VERSION 5.7 ;
  NOWIREEXTENSIONATPIN ON ;
  DIVIDERCHAR "/" ;
  BUSBITCHARS "[]" ;
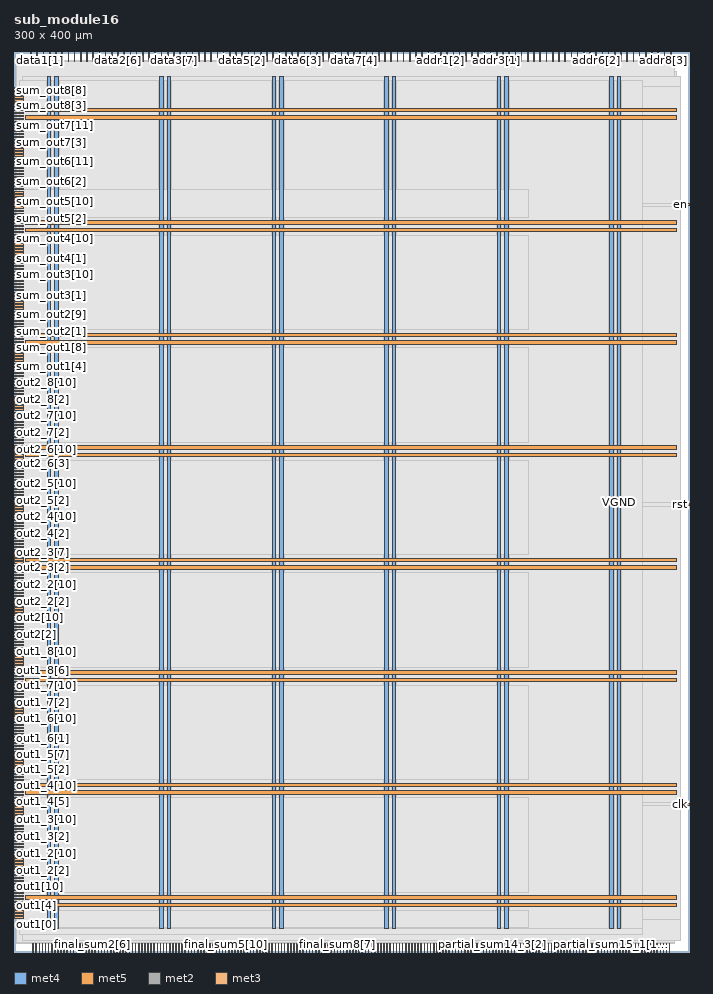
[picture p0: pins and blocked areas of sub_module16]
MACRO sub_module16
  CLASS BLOCK ;
  FOREIGN sub_module16 ;
  ORIGIN 0.000 0.000 ;
  SIZE 300.000 BY 400.000 ;
  PIN VGND
    DIRECTION INOUT ;
    USE GROUND ;
    PORT
      LAYER met4 ;
        RECT 18.020 10.640 19.620 389.200 ;
    END
    PORT
      LAYER met4 ;
        RECT 68.020 10.640 69.620 389.200 ;
    END
    PORT
      LAYER met4 ;
        RECT 118.020 10.640 119.620 389.200 ;
    END
    PORT
      LAYER met4 ;
        RECT 168.020 10.640 169.620 389.200 ;
    END
    PORT
      LAYER met4 ;
        RECT 218.020 10.640 219.620 389.200 ;
    END
    PORT
      LAYER met4 ;
        RECT 268.020 10.640 269.620 389.200 ;
    END
    PORT
      LAYER met5 ;
        RECT 5.280 23.380 294.640 24.980 ;
    END
    PORT
      LAYER met5 ;
        RECT 5.280 73.380 294.640 74.980 ;
    END
    PORT
      LAYER met5 ;
        RECT 5.280 123.380 294.640 124.980 ;
    END
    PORT
      LAYER met5 ;
        RECT 5.280 173.380 294.640 174.980 ;
    END
    PORT
      LAYER met5 ;
        RECT 5.280 223.380 294.640 224.980 ;
    END
    PORT
      LAYER met5 ;
        RECT 5.280 273.380 294.640 274.980 ;
    END
    PORT
      LAYER met5 ;
        RECT 5.280 323.380 294.640 324.980 ;
    END
    PORT
      LAYER met5 ;
        RECT 5.280 373.380 294.640 374.980 ;
    END
  END VGND
  PIN VPWR
    DIRECTION INOUT ;
    USE POWER ;
    PORT
      LAYER met4 ;
        RECT 14.720 10.640 16.320 389.200 ;
    END
    PORT
      LAYER met4 ;
        RECT 64.720 10.640 66.320 389.200 ;
    END
    PORT
      LAYER met4 ;
        RECT 114.720 10.640 116.320 389.200 ;
    END
    PORT
      LAYER met4 ;
        RECT 164.720 10.640 166.320 389.200 ;
    END
    PORT
      LAYER met4 ;
        RECT 214.720 10.640 216.320 389.200 ;
    END
    PORT
      LAYER met4 ;
        RECT 264.720 10.640 266.320 389.200 ;
    END
    PORT
      LAYER met5 ;
        RECT 5.280 20.080 294.640 21.680 ;
    END
    PORT
      LAYER met5 ;
        RECT 5.280 70.080 294.640 71.680 ;
    END
    PORT
      LAYER met5 ;
        RECT 5.280 120.080 294.640 121.680 ;
    END
    PORT
      LAYER met5 ;
        RECT 5.280 170.080 294.640 171.680 ;
    END
    PORT
      LAYER met5 ;
        RECT 5.280 220.080 294.640 221.680 ;
    END
    PORT
      LAYER met5 ;
        RECT 5.280 270.080 294.640 271.680 ;
    END
    PORT
      LAYER met5 ;
        RECT 5.280 320.080 294.640 321.680 ;
    END
    PORT
      LAYER met5 ;
        RECT 5.280 370.080 294.640 371.680 ;
    END
  END VPWR
  PIN addr1[0]
    DIRECTION INPUT ;
    USE SIGNAL ;
    ANTENNAGATEAREA 0.213000 ;
    PORT
      LAYER met2 ;
        RECT 184.090 396.000 184.370 400.000 ;
    END
  END addr1[0]
  PIN addr1[1]
    DIRECTION INPUT ;
    USE SIGNAL ;
    ANTENNAGATEAREA 0.213000 ;
    PORT
      LAYER met2 ;
        RECT 186.850 396.000 187.130 400.000 ;
    END
  END addr1[1]
  PIN addr1[2]
    DIRECTION INPUT ;
    USE SIGNAL ;
    ANTENNAGATEAREA 0.247500 ;
    PORT
      LAYER met2 ;
        RECT 189.610 396.000 189.890 400.000 ;
    END
  END addr1[2]
  PIN addr1[3]
    DIRECTION INPUT ;
    USE SIGNAL ;
    ANTENNAGATEAREA 0.159000 ;
    PORT
      LAYER met2 ;
        RECT 192.370 396.000 192.650 400.000 ;
    END
  END addr1[3]
  PIN addr1[4]
    DIRECTION INPUT ;
    USE SIGNAL ;
    ANTENNAGATEAREA 0.159000 ;
    PORT
      LAYER met2 ;
        RECT 195.130 396.000 195.410 400.000 ;
    END
  END addr1[4]
  PIN addr2[0]
    DIRECTION INPUT ;
    USE SIGNAL ;
    ANTENNAGATEAREA 0.213000 ;
    PORT
      LAYER met2 ;
        RECT 197.890 396.000 198.170 400.000 ;
    END
  END addr2[0]
  PIN addr2[1]
    DIRECTION INPUT ;
    USE SIGNAL ;
    ANTENNAGATEAREA 0.159000 ;
    PORT
      LAYER met2 ;
        RECT 200.650 396.000 200.930 400.000 ;
    END
  END addr2[1]
  PIN addr2[2]
    DIRECTION INPUT ;
    USE SIGNAL ;
    ANTENNAGATEAREA 0.247500 ;
    PORT
      LAYER met2 ;
        RECT 203.410 396.000 203.690 400.000 ;
    END
  END addr2[2]
  PIN addr2[3]
    DIRECTION INPUT ;
    USE SIGNAL ;
    ANTENNAGATEAREA 0.213000 ;
    PORT
      LAYER met2 ;
        RECT 206.170 396.000 206.450 400.000 ;
    END
  END addr2[3]
  PIN addr2[4]
    DIRECTION INPUT ;
    USE SIGNAL ;
    ANTENNAGATEAREA 0.159000 ;
    PORT
      LAYER met2 ;
        RECT 208.930 396.000 209.210 400.000 ;
    END
  END addr2[4]
  PIN addr3[0]
    DIRECTION INPUT ;
    USE SIGNAL ;
    ANTENNAGATEAREA 0.159000 ;
    PORT
      LAYER met2 ;
        RECT 211.690 396.000 211.970 400.000 ;
    END
  END addr3[0]
  PIN addr3[1]
    DIRECTION INPUT ;
    USE SIGNAL ;
    ANTENNAGATEAREA 0.213000 ;
    PORT
      LAYER met2 ;
        RECT 214.450 396.000 214.730 400.000 ;
    END
  END addr3[1]
  PIN addr3[2]
    DIRECTION INPUT ;
    USE SIGNAL ;
    ANTENNAGATEAREA 0.159000 ;
    PORT
      LAYER met2 ;
        RECT 217.210 396.000 217.490 400.000 ;
    END
  END addr3[2]
  PIN addr3[3]
    DIRECTION INPUT ;
    USE SIGNAL ;
    ANTENNAGATEAREA 0.213000 ;
    PORT
      LAYER met2 ;
        RECT 219.970 396.000 220.250 400.000 ;
    END
  END addr3[3]
  PIN addr3[4]
    DIRECTION INPUT ;
    USE SIGNAL ;
    ANTENNAGATEAREA 0.213000 ;
    PORT
      LAYER met2 ;
        RECT 222.730 396.000 223.010 400.000 ;
    END
  END addr3[4]
  PIN addr4[0]
    DIRECTION INPUT ;
    USE SIGNAL ;
    ANTENNAGATEAREA 0.213000 ;
    PORT
      LAYER met2 ;
        RECT 225.490 396.000 225.770 400.000 ;
    END
  END addr4[0]
  PIN addr4[1]
    DIRECTION INPUT ;
    USE SIGNAL ;
    ANTENNAGATEAREA 0.159000 ;
    PORT
      LAYER met2 ;
        RECT 228.250 396.000 228.530 400.000 ;
    END
  END addr4[1]
  PIN addr4[2]
    DIRECTION INPUT ;
    USE SIGNAL ;
    ANTENNAGATEAREA 0.213000 ;
    PORT
      LAYER met2 ;
        RECT 231.010 396.000 231.290 400.000 ;
    END
  END addr4[2]
  PIN addr4[3]
    DIRECTION INPUT ;
    USE SIGNAL ;
    ANTENNAGATEAREA 0.159000 ;
    PORT
      LAYER met2 ;
        RECT 233.770 396.000 234.050 400.000 ;
    END
  END addr4[3]
  PIN addr4[4]
    DIRECTION INPUT ;
    USE SIGNAL ;
    ANTENNAGATEAREA 0.213000 ;
    PORT
      LAYER met2 ;
        RECT 236.530 396.000 236.810 400.000 ;
    END
  END addr4[4]
  PIN addr5[0]
    DIRECTION INPUT ;
    USE SIGNAL ;
    ANTENNAGATEAREA 0.213000 ;
    PORT
      LAYER met2 ;
        RECT 239.290 396.000 239.570 400.000 ;
    END
  END addr5[0]
  PIN addr5[1]
    DIRECTION INPUT ;
    USE SIGNAL ;
    ANTENNAGATEAREA 0.213000 ;
    PORT
      LAYER met2 ;
        RECT 242.050 396.000 242.330 400.000 ;
    END
  END addr5[1]
  PIN addr5[2]
    DIRECTION INPUT ;
    USE SIGNAL ;
    ANTENNAGATEAREA 0.213000 ;
    PORT
      LAYER met2 ;
        RECT 244.810 396.000 245.090 400.000 ;
    END
  END addr5[2]
  PIN addr5[3]
    DIRECTION INPUT ;
    USE SIGNAL ;
    ANTENNAGATEAREA 0.159000 ;
    PORT
      LAYER met2 ;
        RECT 247.570 396.000 247.850 400.000 ;
    END
  END addr5[3]
  PIN addr5[4]
    DIRECTION INPUT ;
    USE SIGNAL ;
    ANTENNAGATEAREA 0.247500 ;
    PORT
      LAYER met2 ;
        RECT 250.330 396.000 250.610 400.000 ;
    END
  END addr5[4]
  PIN addr6[0]
    DIRECTION INPUT ;
    USE SIGNAL ;
    ANTENNAGATEAREA 0.213000 ;
    PORT
      LAYER met2 ;
        RECT 253.090 396.000 253.370 400.000 ;
    END
  END addr6[0]
  PIN addr6[1]
    DIRECTION INPUT ;
    USE SIGNAL ;
    ANTENNAGATEAREA 0.159000 ;
    PORT
      LAYER met2 ;
        RECT 255.850 396.000 256.130 400.000 ;
    END
  END addr6[1]
  PIN addr6[2]
    DIRECTION INPUT ;
    USE SIGNAL ;
    ANTENNAGATEAREA 0.159000 ;
    PORT
      LAYER met2 ;
        RECT 258.610 396.000 258.890 400.000 ;
    END
  END addr6[2]
  PIN addr6[3]
    DIRECTION INPUT ;
    USE SIGNAL ;
    ANTENNAGATEAREA 0.213000 ;
    PORT
      LAYER met2 ;
        RECT 261.370 396.000 261.650 400.000 ;
    END
  END addr6[3]
  PIN addr6[4]
    DIRECTION INPUT ;
    USE SIGNAL ;
    ANTENNAGATEAREA 0.213000 ;
    PORT
      LAYER met2 ;
        RECT 264.130 396.000 264.410 400.000 ;
    END
  END addr6[4]
  PIN addr7[0]
    DIRECTION INPUT ;
    USE SIGNAL ;
    ANTENNAGATEAREA 0.196500 ;
    PORT
      LAYER met2 ;
        RECT 266.890 396.000 267.170 400.000 ;
    END
  END addr7[0]
  PIN addr7[1]
    DIRECTION INPUT ;
    USE SIGNAL ;
    ANTENNAGATEAREA 0.196500 ;
    PORT
      LAYER met2 ;
        RECT 269.650 396.000 269.930 400.000 ;
    END
  END addr7[1]
  PIN addr7[2]
    DIRECTION INPUT ;
    USE SIGNAL ;
    ANTENNAGATEAREA 0.213000 ;
    PORT
      LAYER met2 ;
        RECT 272.410 396.000 272.690 400.000 ;
    END
  END addr7[2]
  PIN addr7[3]
    DIRECTION INPUT ;
    USE SIGNAL ;
    ANTENNAGATEAREA 0.159000 ;
    PORT
      LAYER met2 ;
        RECT 275.170 396.000 275.450 400.000 ;
    END
  END addr7[3]
  PIN addr7[4]
    DIRECTION INPUT ;
    USE SIGNAL ;
    ANTENNAGATEAREA 0.213000 ;
    PORT
      LAYER met2 ;
        RECT 277.930 396.000 278.210 400.000 ;
    END
  END addr7[4]
  PIN addr8[0]
    DIRECTION INPUT ;
    USE SIGNAL ;
    ANTENNAGATEAREA 0.159000 ;
    PORT
      LAYER met2 ;
        RECT 280.690 396.000 280.970 400.000 ;
    END
  END addr8[0]
  PIN addr8[1]
    DIRECTION INPUT ;
    USE SIGNAL ;
    ANTENNAGATEAREA 0.213000 ;
    PORT
      LAYER met2 ;
        RECT 283.450 396.000 283.730 400.000 ;
    END
  END addr8[1]
  PIN addr8[2]
    DIRECTION INPUT ;
    USE SIGNAL ;
    ANTENNAGATEAREA 0.126000 ;
    PORT
      LAYER met2 ;
        RECT 286.210 396.000 286.490 400.000 ;
    END
  END addr8[2]
  PIN addr8[3]
    DIRECTION INPUT ;
    USE SIGNAL ;
    ANTENNAGATEAREA 0.159000 ;
    PORT
      LAYER met2 ;
        RECT 288.970 396.000 289.250 400.000 ;
    END
  END addr8[3]
  PIN addr8[4]
    DIRECTION INPUT ;
    USE SIGNAL ;
    ANTENNAGATEAREA 0.247500 ;
    PORT
      LAYER met2 ;
        RECT 291.730 396.000 292.010 400.000 ;
    END
  END addr8[4]
  PIN clk
    DIRECTION INPUT ;
    USE SIGNAL ;
    ANTENNAGATEAREA 0.852000 ;
    PORT
      LAYER met3 ;
        RECT 296.000 65.320 300.000 65.920 ;
    END
  END clk
  PIN data1[0]
    DIRECTION INPUT ;
    USE SIGNAL ;
    ANTENNAGATEAREA 0.159000 ;
    PORT
      LAYER met2 ;
        RECT 7.450 396.000 7.730 400.000 ;
    END
  END data1[0]
  PIN data1[1]
    DIRECTION INPUT ;
    USE SIGNAL ;
    ANTENNAGATEAREA 0.159000 ;
    PORT
      LAYER met2 ;
        RECT 10.210 396.000 10.490 400.000 ;
    END
  END data1[1]
  PIN data1[2]
    DIRECTION INPUT ;
    USE SIGNAL ;
    ANTENNAGATEAREA 0.213000 ;
    PORT
      LAYER met2 ;
        RECT 12.970 396.000 13.250 400.000 ;
    END
  END data1[2]
  PIN data1[3]
    DIRECTION INPUT ;
    USE SIGNAL ;
    ANTENNAGATEAREA 0.159000 ;
    PORT
      LAYER met2 ;
        RECT 15.730 396.000 16.010 400.000 ;
    END
  END data1[3]
  PIN data1[4]
    DIRECTION INPUT ;
    USE SIGNAL ;
    ANTENNAGATEAREA 0.159000 ;
    PORT
      LAYER met2 ;
        RECT 18.490 396.000 18.770 400.000 ;
    END
  END data1[4]
  PIN data1[5]
    DIRECTION INPUT ;
    USE SIGNAL ;
    ANTENNAGATEAREA 0.159000 ;
    PORT
      LAYER met2 ;
        RECT 21.250 396.000 21.530 400.000 ;
    END
  END data1[5]
  PIN data1[6]
    DIRECTION INPUT ;
    USE SIGNAL ;
    ANTENNAGATEAREA 0.159000 ;
    PORT
      LAYER met2 ;
        RECT 24.010 396.000 24.290 400.000 ;
    END
  END data1[6]
  PIN data1[7]
    DIRECTION INPUT ;
    USE SIGNAL ;
    ANTENNAGATEAREA 0.159000 ;
    PORT
      LAYER met2 ;
        RECT 26.770 396.000 27.050 400.000 ;
    END
  END data1[7]
  PIN data2[0]
    DIRECTION INPUT ;
    USE SIGNAL ;
    ANTENNAGATEAREA 0.159000 ;
    PORT
      LAYER met2 ;
        RECT 29.530 396.000 29.810 400.000 ;
    END
  END data2[0]
  PIN data2[1]
    DIRECTION INPUT ;
    USE SIGNAL ;
    ANTENNAGATEAREA 0.159000 ;
    PORT
      LAYER met2 ;
        RECT 32.290 396.000 32.570 400.000 ;
    END
  END data2[1]
  PIN data2[2]
    DIRECTION INPUT ;
    USE SIGNAL ;
    ANTENNAGATEAREA 0.159000 ;
    PORT
      LAYER met2 ;
        RECT 35.050 396.000 35.330 400.000 ;
    END
  END data2[2]
  PIN data2[3]
    DIRECTION INPUT ;
    USE SIGNAL ;
    ANTENNAGATEAREA 0.159000 ;
    PORT
      LAYER met2 ;
        RECT 37.810 396.000 38.090 400.000 ;
    END
  END data2[3]
  PIN data2[4]
    DIRECTION INPUT ;
    USE SIGNAL ;
    ANTENNAGATEAREA 0.159000 ;
    PORT
      LAYER met2 ;
        RECT 40.570 396.000 40.850 400.000 ;
    END
  END data2[4]
  PIN data2[5]
    DIRECTION INPUT ;
    USE SIGNAL ;
    ANTENNAGATEAREA 0.159000 ;
    PORT
      LAYER met2 ;
        RECT 43.330 396.000 43.610 400.000 ;
    END
  END data2[5]
  PIN data2[6]
    DIRECTION INPUT ;
    USE SIGNAL ;
    ANTENNAGATEAREA 0.159000 ;
    PORT
      LAYER met2 ;
        RECT 46.090 396.000 46.370 400.000 ;
    END
  END data2[6]
  PIN data2[7]
    DIRECTION INPUT ;
    USE SIGNAL ;
    ANTENNAGATEAREA 0.159000 ;
    PORT
      LAYER met2 ;
        RECT 48.850 396.000 49.130 400.000 ;
    END
  END data2[7]
  PIN data3[0]
    DIRECTION INPUT ;
    USE SIGNAL ;
    ANTENNAGATEAREA 0.196500 ;
    PORT
      LAYER met2 ;
        RECT 51.610 396.000 51.890 400.000 ;
    END
  END data3[0]
  PIN data3[1]
    DIRECTION INPUT ;
    USE SIGNAL ;
    ANTENNAGATEAREA 0.196500 ;
    PORT
      LAYER met2 ;
        RECT 54.370 396.000 54.650 400.000 ;
    END
  END data3[1]
  PIN data3[2]
    DIRECTION INPUT ;
    USE SIGNAL ;
    ANTENNAGATEAREA 0.196500 ;
    PORT
      LAYER met2 ;
        RECT 57.130 396.000 57.410 400.000 ;
    END
  END data3[2]
  PIN data3[3]
    DIRECTION INPUT ;
    USE SIGNAL ;
    ANTENNAGATEAREA 0.196500 ;
    PORT
      LAYER met2 ;
        RECT 59.890 396.000 60.170 400.000 ;
    END
  END data3[3]
  PIN data3[4]
    DIRECTION INPUT ;
    USE SIGNAL ;
    ANTENNAGATEAREA 0.196500 ;
    PORT
      LAYER met2 ;
        RECT 62.650 396.000 62.930 400.000 ;
    END
  END data3[4]
  PIN data3[5]
    DIRECTION INPUT ;
    USE SIGNAL ;
    ANTENNAGATEAREA 0.196500 ;
    PORT
      LAYER met2 ;
        RECT 65.410 396.000 65.690 400.000 ;
    END
  END data3[5]
  PIN data3[6]
    DIRECTION INPUT ;
    USE SIGNAL ;
    ANTENNAGATEAREA 0.196500 ;
    PORT
      LAYER met2 ;
        RECT 68.170 396.000 68.450 400.000 ;
    END
  END data3[6]
  PIN data3[7]
    DIRECTION INPUT ;
    USE SIGNAL ;
    ANTENNAGATEAREA 0.196500 ;
    PORT
      LAYER met2 ;
        RECT 70.930 396.000 71.210 400.000 ;
    END
  END data3[7]
  PIN data4[0]
    DIRECTION INPUT ;
    USE SIGNAL ;
    ANTENNAGATEAREA 0.196500 ;
    PORT
      LAYER met2 ;
        RECT 73.690 396.000 73.970 400.000 ;
    END
  END data4[0]
  PIN data4[1]
    DIRECTION INPUT ;
    USE SIGNAL ;
    ANTENNAGATEAREA 0.196500 ;
    PORT
      LAYER met2 ;
        RECT 76.450 396.000 76.730 400.000 ;
    END
  END data4[1]
  PIN data4[2]
    DIRECTION INPUT ;
    USE SIGNAL ;
    ANTENNAGATEAREA 0.196500 ;
    PORT
      LAYER met2 ;
        RECT 79.210 396.000 79.490 400.000 ;
    END
  END data4[2]
  PIN data4[3]
    DIRECTION INPUT ;
    USE SIGNAL ;
    ANTENNAGATEAREA 0.196500 ;
    PORT
      LAYER met2 ;
        RECT 81.970 396.000 82.250 400.000 ;
    END
  END data4[3]
  PIN data4[4]
    DIRECTION INPUT ;
    USE SIGNAL ;
    ANTENNAGATEAREA 0.196500 ;
    PORT
      LAYER met2 ;
        RECT 84.730 396.000 85.010 400.000 ;
    END
  END data4[4]
  PIN data4[5]
    DIRECTION INPUT ;
    USE SIGNAL ;
    ANTENNAGATEAREA 0.196500 ;
    PORT
      LAYER met2 ;
        RECT 87.490 396.000 87.770 400.000 ;
    END
  END data4[5]
  PIN data4[6]
    DIRECTION INPUT ;
    USE SIGNAL ;
    ANTENNAGATEAREA 0.213000 ;
    PORT
      LAYER met2 ;
        RECT 90.250 396.000 90.530 400.000 ;
    END
  END data4[6]
  PIN data4[7]
    DIRECTION INPUT ;
    USE SIGNAL ;
    ANTENNAGATEAREA 0.213000 ;
    PORT
      LAYER met2 ;
        RECT 93.010 396.000 93.290 400.000 ;
    END
  END data4[7]
  PIN data5[0]
    DIRECTION INPUT ;
    USE SIGNAL ;
    ANTENNAGATEAREA 0.196500 ;
    PORT
      LAYER met2 ;
        RECT 95.770 396.000 96.050 400.000 ;
    END
  END data5[0]
  PIN data5[1]
    DIRECTION INPUT ;
    USE SIGNAL ;
    ANTENNAGATEAREA 0.196500 ;
    PORT
      LAYER met2 ;
        RECT 98.530 396.000 98.810 400.000 ;
    END
  END data5[1]
  PIN data5[2]
    DIRECTION INPUT ;
    USE SIGNAL ;
    ANTENNAGATEAREA 0.196500 ;
    PORT
      LAYER met2 ;
        RECT 101.290 396.000 101.570 400.000 ;
    END
  END data5[2]
  PIN data5[3]
    DIRECTION INPUT ;
    USE SIGNAL ;
    ANTENNAGATEAREA 0.196500 ;
    PORT
      LAYER met2 ;
        RECT 104.050 396.000 104.330 400.000 ;
    END
  END data5[3]
  PIN data5[4]
    DIRECTION INPUT ;
    USE SIGNAL ;
    ANTENNAGATEAREA 0.196500 ;
    PORT
      LAYER met2 ;
        RECT 106.810 396.000 107.090 400.000 ;
    END
  END data5[4]
  PIN data5[5]
    DIRECTION INPUT ;
    USE SIGNAL ;
    ANTENNAGATEAREA 0.196500 ;
    PORT
      LAYER met2 ;
        RECT 109.570 396.000 109.850 400.000 ;
    END
  END data5[5]
  PIN data5[6]
    DIRECTION INPUT ;
    USE SIGNAL ;
    ANTENNAGATEAREA 0.126000 ;
    PORT
      LAYER met2 ;
        RECT 112.330 396.000 112.610 400.000 ;
    END
  END data5[6]
  PIN data5[7]
    DIRECTION INPUT ;
    USE SIGNAL ;
    ANTENNAGATEAREA 0.126000 ;
    PORT
      LAYER met2 ;
        RECT 115.090 396.000 115.370 400.000 ;
    END
  END data5[7]
  PIN data6[0]
    DIRECTION INPUT ;
    USE SIGNAL ;
    ANTENNAGATEAREA 0.196500 ;
    PORT
      LAYER met2 ;
        RECT 117.850 396.000 118.130 400.000 ;
    END
  END data6[0]
  PIN data6[1]
    DIRECTION INPUT ;
    USE SIGNAL ;
    ANTENNAGATEAREA 0.196500 ;
    PORT
      LAYER met2 ;
        RECT 120.610 396.000 120.890 400.000 ;
    END
  END data6[1]
  PIN data6[2]
    DIRECTION INPUT ;
    USE SIGNAL ;
    ANTENNAGATEAREA 0.196500 ;
    PORT
      LAYER met2 ;
        RECT 123.370 396.000 123.650 400.000 ;
    END
  END data6[2]
  PIN data6[3]
    DIRECTION INPUT ;
    USE SIGNAL ;
    ANTENNAGATEAREA 0.196500 ;
    PORT
      LAYER met2 ;
        RECT 126.130 396.000 126.410 400.000 ;
    END
  END data6[3]
  PIN data6[4]
    DIRECTION INPUT ;
    USE SIGNAL ;
    ANTENNAGATEAREA 0.196500 ;
    PORT
      LAYER met2 ;
        RECT 128.890 396.000 129.170 400.000 ;
    END
  END data6[4]
  PIN data6[5]
    DIRECTION INPUT ;
    USE SIGNAL ;
    ANTENNAGATEAREA 0.196500 ;
    PORT
      LAYER met2 ;
        RECT 131.650 396.000 131.930 400.000 ;
    END
  END data6[5]
  PIN data6[6]
    DIRECTION INPUT ;
    USE SIGNAL ;
    ANTENNAGATEAREA 0.196500 ;
    PORT
      LAYER met2 ;
        RECT 134.410 396.000 134.690 400.000 ;
    END
  END data6[6]
  PIN data6[7]
    DIRECTION INPUT ;
    USE SIGNAL ;
    ANTENNAGATEAREA 0.196500 ;
    PORT
      LAYER met2 ;
        RECT 137.170 396.000 137.450 400.000 ;
    END
  END data6[7]
  PIN data7[0]
    DIRECTION INPUT ;
    USE SIGNAL ;
    ANTENNAGATEAREA 0.196500 ;
    PORT
      LAYER met2 ;
        RECT 139.930 396.000 140.210 400.000 ;
    END
  END data7[0]
  PIN data7[1]
    DIRECTION INPUT ;
    USE SIGNAL ;
    ANTENNAGATEAREA 0.196500 ;
    PORT
      LAYER met2 ;
        RECT 142.690 396.000 142.970 400.000 ;
    END
  END data7[1]
  PIN data7[2]
    DIRECTION INPUT ;
    USE SIGNAL ;
    ANTENNAGATEAREA 0.196500 ;
    PORT
      LAYER met2 ;
        RECT 145.450 396.000 145.730 400.000 ;
    END
  END data7[2]
  PIN data7[3]
    DIRECTION INPUT ;
    USE SIGNAL ;
    ANTENNAGATEAREA 0.196500 ;
    PORT
      LAYER met2 ;
        RECT 148.210 396.000 148.490 400.000 ;
    END
  END data7[3]
  PIN data7[4]
    DIRECTION INPUT ;
    USE SIGNAL ;
    ANTENNAGATEAREA 0.196500 ;
    PORT
      LAYER met2 ;
        RECT 150.970 396.000 151.250 400.000 ;
    END
  END data7[4]
  PIN data7[5]
    DIRECTION INPUT ;
    USE SIGNAL ;
    ANTENNAGATEAREA 0.196500 ;
    PORT
      LAYER met2 ;
        RECT 153.730 396.000 154.010 400.000 ;
    END
  END data7[5]
  PIN data7[6]
    DIRECTION INPUT ;
    USE SIGNAL ;
    ANTENNAGATEAREA 0.196500 ;
    PORT
      LAYER met2 ;
        RECT 156.490 396.000 156.770 400.000 ;
    END
  END data7[6]
  PIN data7[7]
    DIRECTION INPUT ;
    USE SIGNAL ;
    ANTENNAGATEAREA 0.196500 ;
    PORT
      LAYER met2 ;
        RECT 159.250 396.000 159.530 400.000 ;
    END
  END data7[7]
  PIN data8[0]
    DIRECTION INPUT ;
    USE SIGNAL ;
    ANTENNAGATEAREA 0.196500 ;
    PORT
      LAYER met2 ;
        RECT 162.010 396.000 162.290 400.000 ;
    END
  END data8[0]
  PIN data8[1]
    DIRECTION INPUT ;
    USE SIGNAL ;
    ANTENNAGATEAREA 0.196500 ;
    PORT
      LAYER met2 ;
        RECT 164.770 396.000 165.050 400.000 ;
    END
  END data8[1]
  PIN data8[2]
    DIRECTION INPUT ;
    USE SIGNAL ;
    ANTENNAGATEAREA 0.196500 ;
    PORT
      LAYER met2 ;
        RECT 167.530 396.000 167.810 400.000 ;
    END
  END data8[2]
  PIN data8[3]
    DIRECTION INPUT ;
    USE SIGNAL ;
    ANTENNAGATEAREA 0.196500 ;
    PORT
      LAYER met2 ;
        RECT 170.290 396.000 170.570 400.000 ;
    END
  END data8[3]
  PIN data8[4]
    DIRECTION INPUT ;
    USE SIGNAL ;
    ANTENNAGATEAREA 0.196500 ;
    PORT
      LAYER met2 ;
        RECT 173.050 396.000 173.330 400.000 ;
    END
  END data8[4]
  PIN data8[5]
    DIRECTION INPUT ;
    USE SIGNAL ;
    ANTENNAGATEAREA 0.196500 ;
    PORT
      LAYER met2 ;
        RECT 175.810 396.000 176.090 400.000 ;
    END
  END data8[5]
  PIN data8[6]
    DIRECTION INPUT ;
    USE SIGNAL ;
    ANTENNAGATEAREA 0.196500 ;
    PORT
      LAYER met2 ;
        RECT 178.570 396.000 178.850 400.000 ;
    END
  END data8[6]
  PIN data8[7]
    DIRECTION INPUT ;
    USE SIGNAL ;
    ANTENNAGATEAREA 0.196500 ;
    PORT
      LAYER met2 ;
        RECT 181.330 396.000 181.610 400.000 ;
    END
  END data8[7]
  PIN en
    DIRECTION INPUT ;
    USE SIGNAL ;
    ANTENNAGATEAREA 0.426000 ;
    PORT
      LAYER met3 ;
        RECT 296.000 331.880 300.000 332.480 ;
    END
  END en
  PIN final_sum1[0]
    DIRECTION OUTPUT ;
    USE SIGNAL ;
    ANTENNADIFFAREA 0.340600 ;
    PORT
      LAYER met2 ;
        RECT 8.370 0.000 8.650 4.000 ;
    END
  END final_sum1[0]
  PIN final_sum1[10]
    DIRECTION OUTPUT ;
    USE SIGNAL ;
    ANTENNADIFFAREA 0.340600 ;
    PORT
      LAYER met2 ;
        RECT 22.170 0.000 22.450 4.000 ;
    END
  END final_sum1[10]
  PIN final_sum1[11]
    DIRECTION OUTPUT ;
    USE SIGNAL ;
    ANTENNADIFFAREA 0.340600 ;
    PORT
      LAYER met2 ;
        RECT 23.550 0.000 23.830 4.000 ;
    END
  END final_sum1[11]
  PIN final_sum1[12]
    DIRECTION OUTPUT ;
    USE SIGNAL ;
    ANTENNADIFFAREA 0.340600 ;
    PORT
      LAYER met2 ;
        RECT 24.930 0.000 25.210 4.000 ;
    END
  END final_sum1[12]
  PIN final_sum1[1]
    DIRECTION OUTPUT ;
    USE SIGNAL ;
    ANTENNADIFFAREA 0.340600 ;
    PORT
      LAYER met2 ;
        RECT 9.750 0.000 10.030 4.000 ;
    END
  END final_sum1[1]
  PIN final_sum1[2]
    DIRECTION OUTPUT ;
    USE SIGNAL ;
    ANTENNADIFFAREA 0.340600 ;
    PORT
      LAYER met2 ;
        RECT 11.130 0.000 11.410 4.000 ;
    END
  END final_sum1[2]
  PIN final_sum1[3]
    DIRECTION OUTPUT ;
    USE SIGNAL ;
    ANTENNADIFFAREA 0.340600 ;
    PORT
      LAYER met2 ;
        RECT 12.510 0.000 12.790 4.000 ;
    END
  END final_sum1[3]
  PIN final_sum1[4]
    DIRECTION OUTPUT ;
    USE SIGNAL ;
    ANTENNADIFFAREA 0.340600 ;
    PORT
      LAYER met2 ;
        RECT 13.890 0.000 14.170 4.000 ;
    END
  END final_sum1[4]
  PIN final_sum1[5]
    DIRECTION OUTPUT ;
    USE SIGNAL ;
    ANTENNADIFFAREA 0.340600 ;
    PORT
      LAYER met2 ;
        RECT 15.270 0.000 15.550 4.000 ;
    END
  END final_sum1[5]
  PIN final_sum1[6]
    DIRECTION OUTPUT ;
    USE SIGNAL ;
    ANTENNADIFFAREA 0.340600 ;
    PORT
      LAYER met2 ;
        RECT 16.650 0.000 16.930 4.000 ;
    END
  END final_sum1[6]
  PIN final_sum1[7]
    DIRECTION OUTPUT ;
    USE SIGNAL ;
    ANTENNADIFFAREA 0.340600 ;
    PORT
      LAYER met2 ;
        RECT 18.030 0.000 18.310 4.000 ;
    END
  END final_sum1[7]
  PIN final_sum1[8]
    DIRECTION OUTPUT ;
    USE SIGNAL ;
    ANTENNADIFFAREA 0.340600 ;
    PORT
      LAYER met2 ;
        RECT 19.410 0.000 19.690 4.000 ;
    END
  END final_sum1[8]
  PIN final_sum1[9]
    DIRECTION OUTPUT ;
    USE SIGNAL ;
    ANTENNADIFFAREA 0.340600 ;
    PORT
      LAYER met2 ;
        RECT 20.790 0.000 21.070 4.000 ;
    END
  END final_sum1[9]
  PIN final_sum2[0]
    DIRECTION OUTPUT ;
    USE SIGNAL ;
    ANTENNADIFFAREA 0.340600 ;
    PORT
      LAYER met2 ;
        RECT 26.310 0.000 26.590 4.000 ;
    END
  END final_sum2[0]
  PIN final_sum2[10]
    DIRECTION OUTPUT ;
    USE SIGNAL ;
    ANTENNADIFFAREA 0.340600 ;
    PORT
      LAYER met2 ;
        RECT 40.110 0.000 40.390 4.000 ;
    END
  END final_sum2[10]
  PIN final_sum2[11]
    DIRECTION OUTPUT ;
    USE SIGNAL ;
    ANTENNADIFFAREA 0.340600 ;
    PORT
      LAYER met2 ;
        RECT 41.490 0.000 41.770 4.000 ;
    END
  END final_sum2[11]
  PIN final_sum2[12]
    DIRECTION OUTPUT ;
    USE SIGNAL ;
    ANTENNADIFFAREA 0.340600 ;
    PORT
      LAYER met2 ;
        RECT 42.870 0.000 43.150 4.000 ;
    END
  END final_sum2[12]
  PIN final_sum2[1]
    DIRECTION OUTPUT ;
    USE SIGNAL ;
    ANTENNADIFFAREA 0.340600 ;
    PORT
      LAYER met2 ;
        RECT 27.690 0.000 27.970 4.000 ;
    END
  END final_sum2[1]
  PIN final_sum2[2]
    DIRECTION OUTPUT ;
    USE SIGNAL ;
    ANTENNADIFFAREA 0.340600 ;
    PORT
      LAYER met2 ;
        RECT 29.070 0.000 29.350 4.000 ;
    END
  END final_sum2[2]
  PIN final_sum2[3]
    DIRECTION OUTPUT ;
    USE SIGNAL ;
    ANTENNADIFFAREA 0.340600 ;
    PORT
      LAYER met2 ;
        RECT 30.450 0.000 30.730 4.000 ;
    END
  END final_sum2[3]
  PIN final_sum2[4]
    DIRECTION OUTPUT ;
    USE SIGNAL ;
    ANTENNADIFFAREA 0.340600 ;
    PORT
      LAYER met2 ;
        RECT 31.830 0.000 32.110 4.000 ;
    END
  END final_sum2[4]
  PIN final_sum2[5]
    DIRECTION OUTPUT ;
    USE SIGNAL ;
    ANTENNADIFFAREA 0.340600 ;
    PORT
      LAYER met2 ;
        RECT 33.210 0.000 33.490 4.000 ;
    END
  END final_sum2[5]
  PIN final_sum2[6]
    DIRECTION OUTPUT ;
    USE SIGNAL ;
    ANTENNADIFFAREA 0.340600 ;
    PORT
      LAYER met2 ;
        RECT 34.590 0.000 34.870 4.000 ;
    END
  END final_sum2[6]
  PIN final_sum2[7]
    DIRECTION OUTPUT ;
    USE SIGNAL ;
    ANTENNADIFFAREA 0.340600 ;
    PORT
      LAYER met2 ;
        RECT 35.970 0.000 36.250 4.000 ;
    END
  END final_sum2[7]
  PIN final_sum2[8]
    DIRECTION OUTPUT ;
    USE SIGNAL ;
    ANTENNADIFFAREA 0.340600 ;
    PORT
      LAYER met2 ;
        RECT 37.350 0.000 37.630 4.000 ;
    END
  END final_sum2[8]
  PIN final_sum2[9]
    DIRECTION OUTPUT ;
    USE SIGNAL ;
    ANTENNADIFFAREA 0.340600 ;
    PORT
      LAYER met2 ;
        RECT 38.730 0.000 39.010 4.000 ;
    END
  END final_sum2[9]
  PIN final_sum3[0]
    DIRECTION OUTPUT ;
    USE SIGNAL ;
    ANTENNADIFFAREA 0.340600 ;
    PORT
      LAYER met2 ;
        RECT 44.250 0.000 44.530 4.000 ;
    END
  END final_sum3[0]
  PIN final_sum3[10]
    DIRECTION OUTPUT ;
    USE SIGNAL ;
    ANTENNADIFFAREA 0.340600 ;
    PORT
      LAYER met2 ;
        RECT 58.050 0.000 58.330 4.000 ;
    END
  END final_sum3[10]
  PIN final_sum3[11]
    DIRECTION OUTPUT ;
    USE SIGNAL ;
    ANTENNADIFFAREA 0.340600 ;
    PORT
      LAYER met2 ;
        RECT 59.430 0.000 59.710 4.000 ;
    END
  END final_sum3[11]
  PIN final_sum3[12]
    DIRECTION OUTPUT ;
    USE SIGNAL ;
    ANTENNADIFFAREA 0.340600 ;
    PORT
      LAYER met2 ;
        RECT 60.810 0.000 61.090 4.000 ;
    END
  END final_sum3[12]
  PIN final_sum3[1]
    DIRECTION OUTPUT ;
    USE SIGNAL ;
    ANTENNADIFFAREA 0.340600 ;
    PORT
      LAYER met2 ;
        RECT 45.630 0.000 45.910 4.000 ;
    END
  END final_sum3[1]
  PIN final_sum3[2]
    DIRECTION OUTPUT ;
    USE SIGNAL ;
    ANTENNADIFFAREA 0.340600 ;
    PORT
      LAYER met2 ;
        RECT 47.010 0.000 47.290 4.000 ;
    END
  END final_sum3[2]
  PIN final_sum3[3]
    DIRECTION OUTPUT ;
    USE SIGNAL ;
    ANTENNADIFFAREA 0.340600 ;
    PORT
      LAYER met2 ;
        RECT 48.390 0.000 48.670 4.000 ;
    END
  END final_sum3[3]
  PIN final_sum3[4]
    DIRECTION OUTPUT ;
    USE SIGNAL ;
    ANTENNADIFFAREA 0.340600 ;
    PORT
      LAYER met2 ;
        RECT 49.770 0.000 50.050 4.000 ;
    END
  END final_sum3[4]
  PIN final_sum3[5]
    DIRECTION OUTPUT ;
    USE SIGNAL ;
    ANTENNADIFFAREA 0.340600 ;
    PORT
      LAYER met2 ;
        RECT 51.150 0.000 51.430 4.000 ;
    END
  END final_sum3[5]
  PIN final_sum3[6]
    DIRECTION OUTPUT ;
    USE SIGNAL ;
    ANTENNADIFFAREA 0.340600 ;
    PORT
      LAYER met2 ;
        RECT 52.530 0.000 52.810 4.000 ;
    END
  END final_sum3[6]
  PIN final_sum3[7]
    DIRECTION OUTPUT ;
    USE SIGNAL ;
    ANTENNADIFFAREA 0.340600 ;
    PORT
      LAYER met2 ;
        RECT 53.910 0.000 54.190 4.000 ;
    END
  END final_sum3[7]
  PIN final_sum3[8]
    DIRECTION OUTPUT ;
    USE SIGNAL ;
    ANTENNADIFFAREA 0.340600 ;
    PORT
      LAYER met2 ;
        RECT 55.290 0.000 55.570 4.000 ;
    END
  END final_sum3[8]
  PIN final_sum3[9]
    DIRECTION OUTPUT ;
    USE SIGNAL ;
    ANTENNADIFFAREA 0.340600 ;
    PORT
      LAYER met2 ;
        RECT 56.670 0.000 56.950 4.000 ;
    END
  END final_sum3[9]
  PIN final_sum4[0]
    DIRECTION OUTPUT ;
    USE SIGNAL ;
    ANTENNADIFFAREA 0.340600 ;
    PORT
      LAYER met2 ;
        RECT 62.190 0.000 62.470 4.000 ;
    END
  END final_sum4[0]
  PIN final_sum4[10]
    DIRECTION OUTPUT ;
    USE SIGNAL ;
    ANTENNADIFFAREA 0.340600 ;
    PORT
      LAYER met2 ;
        RECT 75.990 0.000 76.270 4.000 ;
    END
  END final_sum4[10]
  PIN final_sum4[11]
    DIRECTION OUTPUT ;
    USE SIGNAL ;
    ANTENNADIFFAREA 0.340600 ;
    PORT
      LAYER met2 ;
        RECT 77.370 0.000 77.650 4.000 ;
    END
  END final_sum4[11]
  PIN final_sum4[12]
    DIRECTION OUTPUT ;
    USE SIGNAL ;
    ANTENNADIFFAREA 0.340600 ;
    PORT
      LAYER met2 ;
        RECT 78.750 0.000 79.030 4.000 ;
    END
  END final_sum4[12]
  PIN final_sum4[1]
    DIRECTION OUTPUT ;
    USE SIGNAL ;
    ANTENNADIFFAREA 0.340600 ;
    PORT
      LAYER met2 ;
        RECT 63.570 0.000 63.850 4.000 ;
    END
  END final_sum4[1]
  PIN final_sum4[2]
    DIRECTION OUTPUT ;
    USE SIGNAL ;
    ANTENNADIFFAREA 0.340600 ;
    PORT
      LAYER met2 ;
        RECT 64.950 0.000 65.230 4.000 ;
    END
  END final_sum4[2]
  PIN final_sum4[3]
    DIRECTION OUTPUT ;
    USE SIGNAL ;
    ANTENNADIFFAREA 0.340600 ;
    PORT
      LAYER met2 ;
        RECT 66.330 0.000 66.610 4.000 ;
    END
  END final_sum4[3]
  PIN final_sum4[4]
    DIRECTION OUTPUT ;
    USE SIGNAL ;
    ANTENNADIFFAREA 0.340600 ;
    PORT
      LAYER met2 ;
        RECT 67.710 0.000 67.990 4.000 ;
    END
  END final_sum4[4]
  PIN final_sum4[5]
    DIRECTION OUTPUT ;
    USE SIGNAL ;
    ANTENNADIFFAREA 0.340600 ;
    PORT
      LAYER met2 ;
        RECT 69.090 0.000 69.370 4.000 ;
    END
  END final_sum4[5]
  PIN final_sum4[6]
    DIRECTION OUTPUT ;
    USE SIGNAL ;
    ANTENNADIFFAREA 0.340600 ;
    PORT
      LAYER met2 ;
        RECT 70.470 0.000 70.750 4.000 ;
    END
  END final_sum4[6]
  PIN final_sum4[7]
    DIRECTION OUTPUT ;
    USE SIGNAL ;
    ANTENNADIFFAREA 0.340600 ;
    PORT
      LAYER met2 ;
        RECT 71.850 0.000 72.130 4.000 ;
    END
  END final_sum4[7]
  PIN final_sum4[8]
    DIRECTION OUTPUT ;
    USE SIGNAL ;
    ANTENNADIFFAREA 0.340600 ;
    PORT
      LAYER met2 ;
        RECT 73.230 0.000 73.510 4.000 ;
    END
  END final_sum4[8]
  PIN final_sum4[9]
    DIRECTION OUTPUT ;
    USE SIGNAL ;
    ANTENNADIFFAREA 0.340600 ;
    PORT
      LAYER met2 ;
        RECT 74.610 0.000 74.890 4.000 ;
    END
  END final_sum4[9]
  PIN final_sum5[0]
    DIRECTION OUTPUT ;
    USE SIGNAL ;
    ANTENNADIFFAREA 0.340600 ;
    PORT
      LAYER met2 ;
        RECT 80.130 0.000 80.410 4.000 ;
    END
  END final_sum5[0]
  PIN final_sum5[10]
    DIRECTION OUTPUT ;
    USE SIGNAL ;
    ANTENNADIFFAREA 0.340600 ;
    PORT
      LAYER met2 ;
        RECT 93.930 0.000 94.210 4.000 ;
    END
  END final_sum5[10]
  PIN final_sum5[11]
    DIRECTION OUTPUT ;
    USE SIGNAL ;
    ANTENNADIFFAREA 0.340600 ;
    PORT
      LAYER met2 ;
        RECT 95.310 0.000 95.590 4.000 ;
    END
  END final_sum5[11]
  PIN final_sum5[12]
    DIRECTION OUTPUT ;
    USE SIGNAL ;
    ANTENNADIFFAREA 0.340600 ;
    PORT
      LAYER met2 ;
        RECT 96.690 0.000 96.970 4.000 ;
    END
  END final_sum5[12]
  PIN final_sum5[1]
    DIRECTION OUTPUT ;
    USE SIGNAL ;
    ANTENNADIFFAREA 0.340600 ;
    PORT
      LAYER met2 ;
        RECT 81.510 0.000 81.790 4.000 ;
    END
  END final_sum5[1]
  PIN final_sum5[2]
    DIRECTION OUTPUT ;
    USE SIGNAL ;
    ANTENNADIFFAREA 0.340600 ;
    PORT
      LAYER met2 ;
        RECT 82.890 0.000 83.170 4.000 ;
    END
  END final_sum5[2]
  PIN final_sum5[3]
    DIRECTION OUTPUT ;
    USE SIGNAL ;
    ANTENNADIFFAREA 0.340600 ;
    PORT
      LAYER met2 ;
        RECT 84.270 0.000 84.550 4.000 ;
    END
  END final_sum5[3]
  PIN final_sum5[4]
    DIRECTION OUTPUT ;
    USE SIGNAL ;
    ANTENNADIFFAREA 0.340600 ;
    PORT
      LAYER met2 ;
        RECT 85.650 0.000 85.930 4.000 ;
    END
  END final_sum5[4]
  PIN final_sum5[5]
    DIRECTION OUTPUT ;
    USE SIGNAL ;
    ANTENNADIFFAREA 0.340600 ;
    PORT
      LAYER met2 ;
        RECT 87.030 0.000 87.310 4.000 ;
    END
  END final_sum5[5]
  PIN final_sum5[6]
    DIRECTION OUTPUT ;
    USE SIGNAL ;
    ANTENNADIFFAREA 0.340600 ;
    PORT
      LAYER met2 ;
        RECT 88.410 0.000 88.690 4.000 ;
    END
  END final_sum5[6]
  PIN final_sum5[7]
    DIRECTION OUTPUT ;
    USE SIGNAL ;
    ANTENNADIFFAREA 0.340600 ;
    PORT
      LAYER met2 ;
        RECT 89.790 0.000 90.070 4.000 ;
    END
  END final_sum5[7]
  PIN final_sum5[8]
    DIRECTION OUTPUT ;
    USE SIGNAL ;
    ANTENNADIFFAREA 0.340600 ;
    PORT
      LAYER met2 ;
        RECT 91.170 0.000 91.450 4.000 ;
    END
  END final_sum5[8]
  PIN final_sum5[9]
    DIRECTION OUTPUT ;
    USE SIGNAL ;
    ANTENNADIFFAREA 0.340600 ;
    PORT
      LAYER met2 ;
        RECT 92.550 0.000 92.830 4.000 ;
    END
  END final_sum5[9]
  PIN final_sum6[0]
    DIRECTION OUTPUT ;
    USE SIGNAL ;
    ANTENNADIFFAREA 0.340600 ;
    PORT
      LAYER met2 ;
        RECT 98.070 0.000 98.350 4.000 ;
    END
  END final_sum6[0]
  PIN final_sum6[10]
    DIRECTION OUTPUT ;
    USE SIGNAL ;
    ANTENNADIFFAREA 0.340600 ;
    PORT
      LAYER met2 ;
        RECT 111.870 0.000 112.150 4.000 ;
    END
  END final_sum6[10]
  PIN final_sum6[11]
    DIRECTION OUTPUT ;
    USE SIGNAL ;
    ANTENNADIFFAREA 0.340600 ;
    PORT
      LAYER met2 ;
        RECT 113.250 0.000 113.530 4.000 ;
    END
  END final_sum6[11]
  PIN final_sum6[12]
    DIRECTION OUTPUT ;
    USE SIGNAL ;
    ANTENNADIFFAREA 0.340600 ;
    PORT
      LAYER met2 ;
        RECT 114.630 0.000 114.910 4.000 ;
    END
  END final_sum6[12]
  PIN final_sum6[1]
    DIRECTION OUTPUT ;
    USE SIGNAL ;
    ANTENNADIFFAREA 0.340600 ;
    PORT
      LAYER met2 ;
        RECT 99.450 0.000 99.730 4.000 ;
    END
  END final_sum6[1]
  PIN final_sum6[2]
    DIRECTION OUTPUT ;
    USE SIGNAL ;
    ANTENNADIFFAREA 0.340600 ;
    PORT
      LAYER met2 ;
        RECT 100.830 0.000 101.110 4.000 ;
    END
  END final_sum6[2]
  PIN final_sum6[3]
    DIRECTION OUTPUT ;
    USE SIGNAL ;
    ANTENNADIFFAREA 0.340600 ;
    PORT
      LAYER met2 ;
        RECT 102.210 0.000 102.490 4.000 ;
    END
  END final_sum6[3]
  PIN final_sum6[4]
    DIRECTION OUTPUT ;
    USE SIGNAL ;
    ANTENNADIFFAREA 0.340600 ;
    PORT
      LAYER met2 ;
        RECT 103.590 0.000 103.870 4.000 ;
    END
  END final_sum6[4]
  PIN final_sum6[5]
    DIRECTION OUTPUT ;
    USE SIGNAL ;
    ANTENNADIFFAREA 0.340600 ;
    PORT
      LAYER met2 ;
        RECT 104.970 0.000 105.250 4.000 ;
    END
  END final_sum6[5]
  PIN final_sum6[6]
    DIRECTION OUTPUT ;
    USE SIGNAL ;
    ANTENNADIFFAREA 0.340600 ;
    PORT
      LAYER met2 ;
        RECT 106.350 0.000 106.630 4.000 ;
    END
  END final_sum6[6]
  PIN final_sum6[7]
    DIRECTION OUTPUT ;
    USE SIGNAL ;
    ANTENNADIFFAREA 0.340600 ;
    PORT
      LAYER met2 ;
        RECT 107.730 0.000 108.010 4.000 ;
    END
  END final_sum6[7]
  PIN final_sum6[8]
    DIRECTION OUTPUT ;
    USE SIGNAL ;
    ANTENNADIFFAREA 0.340600 ;
    PORT
      LAYER met2 ;
        RECT 109.110 0.000 109.390 4.000 ;
    END
  END final_sum6[8]
  PIN final_sum6[9]
    DIRECTION OUTPUT ;
    USE SIGNAL ;
    ANTENNADIFFAREA 0.340600 ;
    PORT
      LAYER met2 ;
        RECT 110.490 0.000 110.770 4.000 ;
    END
  END final_sum6[9]
  PIN final_sum7[0]
    DIRECTION OUTPUT ;
    USE SIGNAL ;
    ANTENNADIFFAREA 0.340600 ;
    PORT
      LAYER met2 ;
        RECT 116.010 0.000 116.290 4.000 ;
    END
  END final_sum7[0]
  PIN final_sum7[10]
    DIRECTION OUTPUT ;
    USE SIGNAL ;
    ANTENNADIFFAREA 0.340600 ;
    PORT
      LAYER met2 ;
        RECT 129.810 0.000 130.090 4.000 ;
    END
  END final_sum7[10]
  PIN final_sum7[11]
    DIRECTION OUTPUT ;
    USE SIGNAL ;
    ANTENNADIFFAREA 0.340600 ;
    PORT
      LAYER met2 ;
        RECT 131.190 0.000 131.470 4.000 ;
    END
  END final_sum7[11]
  PIN final_sum7[12]
    DIRECTION OUTPUT ;
    USE SIGNAL ;
    ANTENNADIFFAREA 0.340600 ;
    PORT
      LAYER met2 ;
        RECT 132.570 0.000 132.850 4.000 ;
    END
  END final_sum7[12]
  PIN final_sum7[1]
    DIRECTION OUTPUT ;
    USE SIGNAL ;
    ANTENNADIFFAREA 0.340600 ;
    PORT
      LAYER met2 ;
        RECT 117.390 0.000 117.670 4.000 ;
    END
  END final_sum7[1]
  PIN final_sum7[2]
    DIRECTION OUTPUT ;
    USE SIGNAL ;
    ANTENNADIFFAREA 0.340600 ;
    PORT
      LAYER met2 ;
        RECT 118.770 0.000 119.050 4.000 ;
    END
  END final_sum7[2]
  PIN final_sum7[3]
    DIRECTION OUTPUT ;
    USE SIGNAL ;
    ANTENNADIFFAREA 0.340600 ;
    PORT
      LAYER met2 ;
        RECT 120.150 0.000 120.430 4.000 ;
    END
  END final_sum7[3]
  PIN final_sum7[4]
    DIRECTION OUTPUT ;
    USE SIGNAL ;
    ANTENNADIFFAREA 0.340600 ;
    PORT
      LAYER met2 ;
        RECT 121.530 0.000 121.810 4.000 ;
    END
  END final_sum7[4]
  PIN final_sum7[5]
    DIRECTION OUTPUT ;
    USE SIGNAL ;
    ANTENNADIFFAREA 0.340600 ;
    PORT
      LAYER met2 ;
        RECT 122.910 0.000 123.190 4.000 ;
    END
  END final_sum7[5]
  PIN final_sum7[6]
    DIRECTION OUTPUT ;
    USE SIGNAL ;
    ANTENNADIFFAREA 0.340600 ;
    PORT
      LAYER met2 ;
        RECT 124.290 0.000 124.570 4.000 ;
    END
  END final_sum7[6]
  PIN final_sum7[7]
    DIRECTION OUTPUT ;
    USE SIGNAL ;
    ANTENNADIFFAREA 0.340600 ;
    PORT
      LAYER met2 ;
        RECT 125.670 0.000 125.950 4.000 ;
    END
  END final_sum7[7]
  PIN final_sum7[8]
    DIRECTION OUTPUT ;
    USE SIGNAL ;
    ANTENNADIFFAREA 0.340600 ;
    PORT
      LAYER met2 ;
        RECT 127.050 0.000 127.330 4.000 ;
    END
  END final_sum7[8]
  PIN final_sum7[9]
    DIRECTION OUTPUT ;
    USE SIGNAL ;
    ANTENNADIFFAREA 0.340600 ;
    PORT
      LAYER met2 ;
        RECT 128.430 0.000 128.710 4.000 ;
    END
  END final_sum7[9]
  PIN final_sum8[0]
    DIRECTION OUTPUT ;
    USE SIGNAL ;
    ANTENNADIFFAREA 0.340600 ;
    PORT
      LAYER met2 ;
        RECT 133.950 0.000 134.230 4.000 ;
    END
  END final_sum8[0]
  PIN final_sum8[10]
    DIRECTION OUTPUT ;
    USE SIGNAL ;
    ANTENNADIFFAREA 0.340600 ;
    PORT
      LAYER met2 ;
        RECT 147.750 0.000 148.030 4.000 ;
    END
  END final_sum8[10]
  PIN final_sum8[11]
    DIRECTION OUTPUT ;
    USE SIGNAL ;
    ANTENNADIFFAREA 0.340600 ;
    PORT
      LAYER met2 ;
        RECT 149.130 0.000 149.410 4.000 ;
    END
  END final_sum8[11]
  PIN final_sum8[12]
    DIRECTION OUTPUT ;
    USE SIGNAL ;
    ANTENNADIFFAREA 0.340600 ;
    PORT
      LAYER met2 ;
        RECT 150.510 0.000 150.790 4.000 ;
    END
  END final_sum8[12]
  PIN final_sum8[1]
    DIRECTION OUTPUT ;
    USE SIGNAL ;
    ANTENNADIFFAREA 0.340600 ;
    PORT
      LAYER met2 ;
        RECT 135.330 0.000 135.610 4.000 ;
    END
  END final_sum8[1]
  PIN final_sum8[2]
    DIRECTION OUTPUT ;
    USE SIGNAL ;
    ANTENNADIFFAREA 0.340600 ;
    PORT
      LAYER met2 ;
        RECT 136.710 0.000 136.990 4.000 ;
    END
  END final_sum8[2]
  PIN final_sum8[3]
    DIRECTION OUTPUT ;
    USE SIGNAL ;
    ANTENNADIFFAREA 0.340600 ;
    PORT
      LAYER met2 ;
        RECT 138.090 0.000 138.370 4.000 ;
    END
  END final_sum8[3]
  PIN final_sum8[4]
    DIRECTION OUTPUT ;
    USE SIGNAL ;
    ANTENNADIFFAREA 0.340600 ;
    PORT
      LAYER met2 ;
        RECT 139.470 0.000 139.750 4.000 ;
    END
  END final_sum8[4]
  PIN final_sum8[5]
    DIRECTION OUTPUT ;
    USE SIGNAL ;
    ANTENNADIFFAREA 0.340600 ;
    PORT
      LAYER met2 ;
        RECT 140.850 0.000 141.130 4.000 ;
    END
  END final_sum8[5]
  PIN final_sum8[6]
    DIRECTION OUTPUT ;
    USE SIGNAL ;
    ANTENNADIFFAREA 0.340600 ;
    PORT
      LAYER met2 ;
        RECT 142.230 0.000 142.510 4.000 ;
    END
  END final_sum8[6]
  PIN final_sum8[7]
    DIRECTION OUTPUT ;
    USE SIGNAL ;
    ANTENNADIFFAREA 0.340600 ;
    PORT
      LAYER met2 ;
        RECT 143.610 0.000 143.890 4.000 ;
    END
  END final_sum8[7]
  PIN final_sum8[8]
    DIRECTION OUTPUT ;
    USE SIGNAL ;
    ANTENNADIFFAREA 0.340600 ;
    PORT
      LAYER met2 ;
        RECT 144.990 0.000 145.270 4.000 ;
    END
  END final_sum8[8]
  PIN final_sum8[9]
    DIRECTION OUTPUT ;
    USE SIGNAL ;
    ANTENNADIFFAREA 0.340600 ;
    PORT
      LAYER met2 ;
        RECT 146.370 0.000 146.650 4.000 ;
    END
  END final_sum8[9]
  PIN out1[0]
    DIRECTION OUTPUT ;
    USE SIGNAL ;
    PORT
      LAYER met3 ;
        RECT 0.000 15.000 4.000 15.600 ;
    END
  END out1[0]
  PIN out1[10]
    DIRECTION OUTPUT ;
    USE SIGNAL ;
    ANTENNADIFFAREA 0.340600 ;
    PORT
      LAYER met3 ;
        RECT 0.000 28.600 4.000 29.200 ;
    END
  END out1[10]
  PIN out1[1]
    DIRECTION OUTPUT ;
    USE SIGNAL ;
    ANTENNADIFFAREA 0.340600 ;
    PORT
      LAYER met3 ;
        RECT 0.000 16.360 4.000 16.960 ;
    END
  END out1[1]
  PIN out1[2]
    DIRECTION OUTPUT ;
    USE SIGNAL ;
    ANTENNADIFFAREA 0.340600 ;
    PORT
      LAYER met3 ;
        RECT 0.000 17.720 4.000 18.320 ;
    END
  END out1[2]
  PIN out1[3]
    DIRECTION OUTPUT ;
    USE SIGNAL ;
    ANTENNADIFFAREA 0.340600 ;
    PORT
      LAYER met3 ;
        RECT 0.000 19.080 4.000 19.680 ;
    END
  END out1[3]
  PIN out1[4]
    DIRECTION OUTPUT ;
    USE SIGNAL ;
    ANTENNADIFFAREA 0.340600 ;
    PORT
      LAYER met3 ;
        RECT 0.000 20.440 4.000 21.040 ;
    END
  END out1[4]
  PIN out1[5]
    DIRECTION OUTPUT ;
    USE SIGNAL ;
    ANTENNADIFFAREA 0.340600 ;
    PORT
      LAYER met3 ;
        RECT 0.000 21.800 4.000 22.400 ;
    END
  END out1[5]
  PIN out1[6]
    DIRECTION OUTPUT ;
    USE SIGNAL ;
    ANTENNADIFFAREA 0.340600 ;
    PORT
      LAYER met3 ;
        RECT 0.000 23.160 4.000 23.760 ;
    END
  END out1[6]
  PIN out1[7]
    DIRECTION OUTPUT ;
    USE SIGNAL ;
    ANTENNADIFFAREA 0.340600 ;
    PORT
      LAYER met3 ;
        RECT 0.000 24.520 4.000 25.120 ;
    END
  END out1[7]
  PIN out1[8]
    DIRECTION OUTPUT ;
    USE SIGNAL ;
    ANTENNADIFFAREA 0.340600 ;
    PORT
      LAYER met3 ;
        RECT 0.000 25.880 4.000 26.480 ;
    END
  END out1[8]
  PIN out1[9]
    DIRECTION OUTPUT ;
    USE SIGNAL ;
    ANTENNADIFFAREA 0.340600 ;
    PORT
      LAYER met3 ;
        RECT 0.000 27.240 4.000 27.840 ;
    END
  END out1[9]
  PIN out1_2[0]
    DIRECTION OUTPUT ;
    USE SIGNAL ;
    PORT
      LAYER met3 ;
        RECT 0.000 29.960 4.000 30.560 ;
    END
  END out1_2[0]
  PIN out1_2[10]
    DIRECTION OUTPUT ;
    USE SIGNAL ;
    ANTENNADIFFAREA 0.340600 ;
    PORT
      LAYER met3 ;
        RECT 0.000 43.560 4.000 44.160 ;
    END
  END out1_2[10]
  PIN out1_2[1]
    DIRECTION OUTPUT ;
    USE SIGNAL ;
    ANTENNADIFFAREA 0.340600 ;
    PORT
      LAYER met3 ;
        RECT 0.000 31.320 4.000 31.920 ;
    END
  END out1_2[1]
  PIN out1_2[2]
    DIRECTION OUTPUT ;
    USE SIGNAL ;
    ANTENNADIFFAREA 0.340600 ;
    PORT
      LAYER met3 ;
        RECT 0.000 32.680 4.000 33.280 ;
    END
  END out1_2[2]
  PIN out1_2[3]
    DIRECTION OUTPUT ;
    USE SIGNAL ;
    ANTENNADIFFAREA 0.340600 ;
    PORT
      LAYER met3 ;
        RECT 0.000 34.040 4.000 34.640 ;
    END
  END out1_2[3]
  PIN out1_2[4]
    DIRECTION OUTPUT ;
    USE SIGNAL ;
    ANTENNADIFFAREA 0.340600 ;
    PORT
      LAYER met3 ;
        RECT 0.000 35.400 4.000 36.000 ;
    END
  END out1_2[4]
  PIN out1_2[5]
    DIRECTION OUTPUT ;
    USE SIGNAL ;
    ANTENNADIFFAREA 0.340600 ;
    PORT
      LAYER met3 ;
        RECT 0.000 36.760 4.000 37.360 ;
    END
  END out1_2[5]
  PIN out1_2[6]
    DIRECTION OUTPUT ;
    USE SIGNAL ;
    ANTENNADIFFAREA 0.340600 ;
    PORT
      LAYER met3 ;
        RECT 0.000 38.120 4.000 38.720 ;
    END
  END out1_2[6]
  PIN out1_2[7]
    DIRECTION OUTPUT ;
    USE SIGNAL ;
    ANTENNADIFFAREA 0.340600 ;
    PORT
      LAYER met3 ;
        RECT 0.000 39.480 4.000 40.080 ;
    END
  END out1_2[7]
  PIN out1_2[8]
    DIRECTION OUTPUT ;
    USE SIGNAL ;
    ANTENNADIFFAREA 0.340600 ;
    PORT
      LAYER met3 ;
        RECT 0.000 40.840 4.000 41.440 ;
    END
  END out1_2[8]
  PIN out1_2[9]
    DIRECTION OUTPUT ;
    USE SIGNAL ;
    ANTENNADIFFAREA 0.340600 ;
    PORT
      LAYER met3 ;
        RECT 0.000 42.200 4.000 42.800 ;
    END
  END out1_2[9]
  PIN out1_3[0]
    DIRECTION OUTPUT ;
    USE SIGNAL ;
    PORT
      LAYER met3 ;
        RECT 0.000 44.920 4.000 45.520 ;
    END
  END out1_3[0]
  PIN out1_3[10]
    DIRECTION OUTPUT ;
    USE SIGNAL ;
    ANTENNADIFFAREA 0.340600 ;
    PORT
      LAYER met3 ;
        RECT 0.000 58.520 4.000 59.120 ;
    END
  END out1_3[10]
  PIN out1_3[1]
    DIRECTION OUTPUT ;
    USE SIGNAL ;
    ANTENNADIFFAREA 0.340600 ;
    PORT
      LAYER met3 ;
        RECT 0.000 46.280 4.000 46.880 ;
    END
  END out1_3[1]
  PIN out1_3[2]
    DIRECTION OUTPUT ;
    USE SIGNAL ;
    ANTENNADIFFAREA 0.340600 ;
    PORT
      LAYER met3 ;
        RECT 0.000 47.640 4.000 48.240 ;
    END
  END out1_3[2]
  PIN out1_3[3]
    DIRECTION OUTPUT ;
    USE SIGNAL ;
    ANTENNADIFFAREA 0.340600 ;
    PORT
      LAYER met3 ;
        RECT 0.000 49.000 4.000 49.600 ;
    END
  END out1_3[3]
  PIN out1_3[4]
    DIRECTION OUTPUT ;
    USE SIGNAL ;
    ANTENNADIFFAREA 0.340600 ;
    PORT
      LAYER met3 ;
        RECT 0.000 50.360 4.000 50.960 ;
    END
  END out1_3[4]
  PIN out1_3[5]
    DIRECTION OUTPUT ;
    USE SIGNAL ;
    ANTENNADIFFAREA 0.340600 ;
    PORT
      LAYER met3 ;
        RECT 0.000 51.720 4.000 52.320 ;
    END
  END out1_3[5]
  PIN out1_3[6]
    DIRECTION OUTPUT ;
    USE SIGNAL ;
    ANTENNADIFFAREA 0.340600 ;
    PORT
      LAYER met3 ;
        RECT 0.000 53.080 4.000 53.680 ;
    END
  END out1_3[6]
  PIN out1_3[7]
    DIRECTION OUTPUT ;
    USE SIGNAL ;
    ANTENNADIFFAREA 0.340600 ;
    PORT
      LAYER met3 ;
        RECT 0.000 54.440 4.000 55.040 ;
    END
  END out1_3[7]
  PIN out1_3[8]
    DIRECTION OUTPUT ;
    USE SIGNAL ;
    ANTENNADIFFAREA 0.340600 ;
    PORT
      LAYER met3 ;
        RECT 0.000 55.800 4.000 56.400 ;
    END
  END out1_3[8]
  PIN out1_3[9]
    DIRECTION OUTPUT ;
    USE SIGNAL ;
    ANTENNADIFFAREA 0.340600 ;
    PORT
      LAYER met3 ;
        RECT 0.000 57.160 4.000 57.760 ;
    END
  END out1_3[9]
  PIN out1_4[0]
    DIRECTION OUTPUT ;
    USE SIGNAL ;
    PORT
      LAYER met3 ;
        RECT 0.000 59.880 4.000 60.480 ;
    END
  END out1_4[0]
  PIN out1_4[10]
    DIRECTION OUTPUT ;
    USE SIGNAL ;
    ANTENNADIFFAREA 0.340600 ;
    PORT
      LAYER met3 ;
        RECT 0.000 73.480 4.000 74.080 ;
    END
  END out1_4[10]
  PIN out1_4[1]
    DIRECTION OUTPUT ;
    USE SIGNAL ;
    ANTENNADIFFAREA 0.340600 ;
    PORT
      LAYER met3 ;
        RECT 0.000 61.240 4.000 61.840 ;
    END
  END out1_4[1]
  PIN out1_4[2]
    DIRECTION OUTPUT ;
    USE SIGNAL ;
    ANTENNADIFFAREA 0.340600 ;
    PORT
      LAYER met3 ;
        RECT 0.000 62.600 4.000 63.200 ;
    END
  END out1_4[2]
  PIN out1_4[3]
    DIRECTION OUTPUT ;
    USE SIGNAL ;
    ANTENNADIFFAREA 0.340600 ;
    PORT
      LAYER met3 ;
        RECT 0.000 63.960 4.000 64.560 ;
    END
  END out1_4[3]
  PIN out1_4[4]
    DIRECTION OUTPUT ;
    USE SIGNAL ;
    ANTENNADIFFAREA 0.340600 ;
    PORT
      LAYER met3 ;
        RECT 0.000 65.320 4.000 65.920 ;
    END
  END out1_4[4]
  PIN out1_4[5]
    DIRECTION OUTPUT ;
    USE SIGNAL ;
    ANTENNADIFFAREA 0.340600 ;
    PORT
      LAYER met3 ;
        RECT 0.000 66.680 4.000 67.280 ;
    END
  END out1_4[5]
  PIN out1_4[6]
    DIRECTION OUTPUT ;
    USE SIGNAL ;
    ANTENNADIFFAREA 0.340600 ;
    PORT
      LAYER met3 ;
        RECT 0.000 68.040 4.000 68.640 ;
    END
  END out1_4[6]
  PIN out1_4[7]
    DIRECTION OUTPUT ;
    USE SIGNAL ;
    ANTENNADIFFAREA 0.340600 ;
    PORT
      LAYER met3 ;
        RECT 0.000 69.400 4.000 70.000 ;
    END
  END out1_4[7]
  PIN out1_4[8]
    DIRECTION OUTPUT ;
    USE SIGNAL ;
    ANTENNADIFFAREA 0.340600 ;
    PORT
      LAYER met3 ;
        RECT 0.000 70.760 4.000 71.360 ;
    END
  END out1_4[8]
  PIN out1_4[9]
    DIRECTION OUTPUT ;
    USE SIGNAL ;
    ANTENNADIFFAREA 0.340600 ;
    PORT
      LAYER met3 ;
        RECT 0.000 72.120 4.000 72.720 ;
    END
  END out1_4[9]
  PIN out1_5[0]
    DIRECTION OUTPUT ;
    USE SIGNAL ;
    PORT
      LAYER met3 ;
        RECT 0.000 74.840 4.000 75.440 ;
    END
  END out1_5[0]
  PIN out1_5[10]
    DIRECTION OUTPUT ;
    USE SIGNAL ;
    ANTENNADIFFAREA 0.340600 ;
    PORT
      LAYER met3 ;
        RECT 0.000 88.440 4.000 89.040 ;
    END
  END out1_5[10]
  PIN out1_5[1]
    DIRECTION OUTPUT ;
    USE SIGNAL ;
    ANTENNADIFFAREA 0.340600 ;
    PORT
      LAYER met3 ;
        RECT 0.000 76.200 4.000 76.800 ;
    END
  END out1_5[1]
  PIN out1_5[2]
    DIRECTION OUTPUT ;
    USE SIGNAL ;
    ANTENNADIFFAREA 0.340600 ;
    PORT
      LAYER met3 ;
        RECT 0.000 77.560 4.000 78.160 ;
    END
  END out1_5[2]
  PIN out1_5[3]
    DIRECTION OUTPUT ;
    USE SIGNAL ;
    ANTENNADIFFAREA 0.340600 ;
    PORT
      LAYER met3 ;
        RECT 0.000 78.920 4.000 79.520 ;
    END
  END out1_5[3]
  PIN out1_5[4]
    DIRECTION OUTPUT ;
    USE SIGNAL ;
    ANTENNADIFFAREA 0.340600 ;
    PORT
      LAYER met3 ;
        RECT 0.000 80.280 4.000 80.880 ;
    END
  END out1_5[4]
  PIN out1_5[5]
    DIRECTION OUTPUT ;
    USE SIGNAL ;
    ANTENNADIFFAREA 0.340600 ;
    PORT
      LAYER met3 ;
        RECT 0.000 81.640 4.000 82.240 ;
    END
  END out1_5[5]
  PIN out1_5[6]
    DIRECTION OUTPUT ;
    USE SIGNAL ;
    ANTENNADIFFAREA 0.340600 ;
    PORT
      LAYER met3 ;
        RECT 0.000 83.000 4.000 83.600 ;
    END
  END out1_5[6]
  PIN out1_5[7]
    DIRECTION OUTPUT ;
    USE SIGNAL ;
    ANTENNADIFFAREA 0.340600 ;
    PORT
      LAYER met3 ;
        RECT 0.000 84.360 4.000 84.960 ;
    END
  END out1_5[7]
  PIN out1_5[8]
    DIRECTION OUTPUT ;
    USE SIGNAL ;
    ANTENNADIFFAREA 0.340600 ;
    PORT
      LAYER met3 ;
        RECT 0.000 85.720 4.000 86.320 ;
    END
  END out1_5[8]
  PIN out1_5[9]
    DIRECTION OUTPUT ;
    USE SIGNAL ;
    ANTENNADIFFAREA 0.340600 ;
    PORT
      LAYER met3 ;
        RECT 0.000 87.080 4.000 87.680 ;
    END
  END out1_5[9]
  PIN out1_6[0]
    DIRECTION OUTPUT ;
    USE SIGNAL ;
    PORT
      LAYER met3 ;
        RECT 0.000 89.800 4.000 90.400 ;
    END
  END out1_6[0]
  PIN out1_6[10]
    DIRECTION OUTPUT ;
    USE SIGNAL ;
    ANTENNADIFFAREA 0.340600 ;
    PORT
      LAYER met3 ;
        RECT 0.000 103.400 4.000 104.000 ;
    END
  END out1_6[10]
  PIN out1_6[1]
    DIRECTION OUTPUT ;
    USE SIGNAL ;
    ANTENNADIFFAREA 0.340600 ;
    PORT
      LAYER met3 ;
        RECT 0.000 91.160 4.000 91.760 ;
    END
  END out1_6[1]
  PIN out1_6[2]
    DIRECTION OUTPUT ;
    USE SIGNAL ;
    ANTENNADIFFAREA 0.340600 ;
    PORT
      LAYER met3 ;
        RECT 0.000 92.520 4.000 93.120 ;
    END
  END out1_6[2]
  PIN out1_6[3]
    DIRECTION OUTPUT ;
    USE SIGNAL ;
    ANTENNADIFFAREA 0.340600 ;
    PORT
      LAYER met3 ;
        RECT 0.000 93.880 4.000 94.480 ;
    END
  END out1_6[3]
  PIN out1_6[4]
    DIRECTION OUTPUT ;
    USE SIGNAL ;
    ANTENNADIFFAREA 0.340600 ;
    PORT
      LAYER met3 ;
        RECT 0.000 95.240 4.000 95.840 ;
    END
  END out1_6[4]
  PIN out1_6[5]
    DIRECTION OUTPUT ;
    USE SIGNAL ;
    ANTENNADIFFAREA 0.340600 ;
    PORT
      LAYER met3 ;
        RECT 0.000 96.600 4.000 97.200 ;
    END
  END out1_6[5]
  PIN out1_6[6]
    DIRECTION OUTPUT ;
    USE SIGNAL ;
    ANTENNADIFFAREA 0.340600 ;
    PORT
      LAYER met3 ;
        RECT 0.000 97.960 4.000 98.560 ;
    END
  END out1_6[6]
  PIN out1_6[7]
    DIRECTION OUTPUT ;
    USE SIGNAL ;
    ANTENNADIFFAREA 0.340600 ;
    PORT
      LAYER met3 ;
        RECT 0.000 99.320 4.000 99.920 ;
    END
  END out1_6[7]
  PIN out1_6[8]
    DIRECTION OUTPUT ;
    USE SIGNAL ;
    ANTENNADIFFAREA 0.340600 ;
    PORT
      LAYER met3 ;
        RECT 0.000 100.680 4.000 101.280 ;
    END
  END out1_6[8]
  PIN out1_6[9]
    DIRECTION OUTPUT ;
    USE SIGNAL ;
    ANTENNADIFFAREA 0.340600 ;
    PORT
      LAYER met3 ;
        RECT 0.000 102.040 4.000 102.640 ;
    END
  END out1_6[9]
  PIN out1_7[0]
    DIRECTION OUTPUT ;
    USE SIGNAL ;
    PORT
      LAYER met3 ;
        RECT 0.000 104.760 4.000 105.360 ;
    END
  END out1_7[0]
  PIN out1_7[10]
    DIRECTION OUTPUT ;
    USE SIGNAL ;
    ANTENNADIFFAREA 0.340600 ;
    PORT
      LAYER met3 ;
        RECT 0.000 118.360 4.000 118.960 ;
    END
  END out1_7[10]
  PIN out1_7[1]
    DIRECTION OUTPUT ;
    USE SIGNAL ;
    ANTENNADIFFAREA 0.340600 ;
    PORT
      LAYER met3 ;
        RECT 0.000 106.120 4.000 106.720 ;
    END
  END out1_7[1]
  PIN out1_7[2]
    DIRECTION OUTPUT ;
    USE SIGNAL ;
    ANTENNADIFFAREA 0.340600 ;
    PORT
      LAYER met3 ;
        RECT 0.000 107.480 4.000 108.080 ;
    END
  END out1_7[2]
  PIN out1_7[3]
    DIRECTION OUTPUT ;
    USE SIGNAL ;
    ANTENNADIFFAREA 0.340600 ;
    PORT
      LAYER met3 ;
        RECT 0.000 108.840 4.000 109.440 ;
    END
  END out1_7[3]
  PIN out1_7[4]
    DIRECTION OUTPUT ;
    USE SIGNAL ;
    ANTENNADIFFAREA 0.340600 ;
    PORT
      LAYER met3 ;
        RECT 0.000 110.200 4.000 110.800 ;
    END
  END out1_7[4]
  PIN out1_7[5]
    DIRECTION OUTPUT ;
    USE SIGNAL ;
    ANTENNADIFFAREA 0.340600 ;
    PORT
      LAYER met3 ;
        RECT 0.000 111.560 4.000 112.160 ;
    END
  END out1_7[5]
  PIN out1_7[6]
    DIRECTION OUTPUT ;
    USE SIGNAL ;
    ANTENNADIFFAREA 0.340600 ;
    PORT
      LAYER met3 ;
        RECT 0.000 112.920 4.000 113.520 ;
    END
  END out1_7[6]
  PIN out1_7[7]
    DIRECTION OUTPUT ;
    USE SIGNAL ;
    ANTENNADIFFAREA 0.340600 ;
    PORT
      LAYER met3 ;
        RECT 0.000 114.280 4.000 114.880 ;
    END
  END out1_7[7]
  PIN out1_7[8]
    DIRECTION OUTPUT ;
    USE SIGNAL ;
    ANTENNADIFFAREA 0.340600 ;
    PORT
      LAYER met3 ;
        RECT 0.000 115.640 4.000 116.240 ;
    END
  END out1_7[8]
  PIN out1_7[9]
    DIRECTION OUTPUT ;
    USE SIGNAL ;
    ANTENNADIFFAREA 0.340600 ;
    PORT
      LAYER met3 ;
        RECT 0.000 117.000 4.000 117.600 ;
    END
  END out1_7[9]
  PIN out1_8[0]
    DIRECTION OUTPUT ;
    USE SIGNAL ;
    PORT
      LAYER met3 ;
        RECT 0.000 119.720 4.000 120.320 ;
    END
  END out1_8[0]
  PIN out1_8[10]
    DIRECTION OUTPUT ;
    USE SIGNAL ;
    ANTENNADIFFAREA 0.340600 ;
    PORT
      LAYER met3 ;
        RECT 0.000 133.320 4.000 133.920 ;
    END
  END out1_8[10]
  PIN out1_8[1]
    DIRECTION OUTPUT ;
    USE SIGNAL ;
    ANTENNADIFFAREA 0.340600 ;
    PORT
      LAYER met3 ;
        RECT 0.000 121.080 4.000 121.680 ;
    END
  END out1_8[1]
  PIN out1_8[2]
    DIRECTION OUTPUT ;
    USE SIGNAL ;
    ANTENNADIFFAREA 0.340600 ;
    PORT
      LAYER met3 ;
        RECT 0.000 122.440 4.000 123.040 ;
    END
  END out1_8[2]
  PIN out1_8[3]
    DIRECTION OUTPUT ;
    USE SIGNAL ;
    ANTENNADIFFAREA 0.340600 ;
    PORT
      LAYER met3 ;
        RECT 0.000 123.800 4.000 124.400 ;
    END
  END out1_8[3]
  PIN out1_8[4]
    DIRECTION OUTPUT ;
    USE SIGNAL ;
    ANTENNADIFFAREA 0.340600 ;
    PORT
      LAYER met3 ;
        RECT 0.000 125.160 4.000 125.760 ;
    END
  END out1_8[4]
  PIN out1_8[5]
    DIRECTION OUTPUT ;
    USE SIGNAL ;
    ANTENNADIFFAREA 0.340600 ;
    PORT
      LAYER met3 ;
        RECT 0.000 126.520 4.000 127.120 ;
    END
  END out1_8[5]
  PIN out1_8[6]
    DIRECTION OUTPUT ;
    USE SIGNAL ;
    ANTENNADIFFAREA 0.340600 ;
    PORT
      LAYER met3 ;
        RECT 0.000 127.880 4.000 128.480 ;
    END
  END out1_8[6]
  PIN out1_8[7]
    DIRECTION OUTPUT ;
    USE SIGNAL ;
    ANTENNADIFFAREA 0.340600 ;
    PORT
      LAYER met3 ;
        RECT 0.000 129.240 4.000 129.840 ;
    END
  END out1_8[7]
  PIN out1_8[8]
    DIRECTION OUTPUT ;
    USE SIGNAL ;
    ANTENNADIFFAREA 0.340600 ;
    PORT
      LAYER met3 ;
        RECT 0.000 130.600 4.000 131.200 ;
    END
  END out1_8[8]
  PIN out1_8[9]
    DIRECTION OUTPUT ;
    USE SIGNAL ;
    ANTENNADIFFAREA 0.340600 ;
    PORT
      LAYER met3 ;
        RECT 0.000 131.960 4.000 132.560 ;
    END
  END out1_8[9]
  PIN out2[0]
    DIRECTION OUTPUT ;
    USE SIGNAL ;
    ANTENNADIFFAREA 0.340600 ;
    PORT
      LAYER met3 ;
        RECT 0.000 134.680 4.000 135.280 ;
    END
  END out2[0]
  PIN out2[10]
    DIRECTION OUTPUT ;
    USE SIGNAL ;
    ANTENNADIFFAREA 0.340600 ;
    PORT
      LAYER met3 ;
        RECT 0.000 148.280 4.000 148.880 ;
    END
  END out2[10]
  PIN out2[1]
    DIRECTION OUTPUT ;
    USE SIGNAL ;
    ANTENNADIFFAREA 0.340600 ;
    PORT
      LAYER met3 ;
        RECT 0.000 136.040 4.000 136.640 ;
    END
  END out2[1]
  PIN out2[2]
    DIRECTION OUTPUT ;
    USE SIGNAL ;
    ANTENNADIFFAREA 0.340600 ;
    PORT
      LAYER met3 ;
        RECT 0.000 137.400 4.000 138.000 ;
    END
  END out2[2]
  PIN out2[3]
    DIRECTION OUTPUT ;
    USE SIGNAL ;
    ANTENNADIFFAREA 0.340600 ;
    PORT
      LAYER met3 ;
        RECT 0.000 138.760 4.000 139.360 ;
    END
  END out2[3]
  PIN out2[4]
    DIRECTION OUTPUT ;
    USE SIGNAL ;
    ANTENNADIFFAREA 0.340600 ;
    PORT
      LAYER met3 ;
        RECT 0.000 140.120 4.000 140.720 ;
    END
  END out2[4]
  PIN out2[5]
    DIRECTION OUTPUT ;
    USE SIGNAL ;
    ANTENNADIFFAREA 0.340600 ;
    PORT
      LAYER met3 ;
        RECT 0.000 141.480 4.000 142.080 ;
    END
  END out2[5]
  PIN out2[6]
    DIRECTION OUTPUT ;
    USE SIGNAL ;
    ANTENNADIFFAREA 0.340600 ;
    PORT
      LAYER met3 ;
        RECT 0.000 142.840 4.000 143.440 ;
    END
  END out2[6]
  PIN out2[7]
    DIRECTION OUTPUT ;
    USE SIGNAL ;
    ANTENNADIFFAREA 0.340600 ;
    PORT
      LAYER met3 ;
        RECT 0.000 144.200 4.000 144.800 ;
    END
  END out2[7]
  PIN out2[8]
    DIRECTION OUTPUT ;
    USE SIGNAL ;
    ANTENNADIFFAREA 0.340600 ;
    PORT
      LAYER met3 ;
        RECT 0.000 145.560 4.000 146.160 ;
    END
  END out2[8]
  PIN out2[9]
    DIRECTION OUTPUT ;
    USE SIGNAL ;
    ANTENNADIFFAREA 0.340600 ;
    PORT
      LAYER met3 ;
        RECT 0.000 146.920 4.000 147.520 ;
    END
  END out2[9]
  PIN out2_2[0]
    DIRECTION OUTPUT ;
    USE SIGNAL ;
    ANTENNADIFFAREA 0.340600 ;
    PORT
      LAYER met3 ;
        RECT 0.000 149.640 4.000 150.240 ;
    END
  END out2_2[0]
  PIN out2_2[10]
    DIRECTION OUTPUT ;
    USE SIGNAL ;
    ANTENNADIFFAREA 0.340600 ;
    PORT
      LAYER met3 ;
        RECT 0.000 163.240 4.000 163.840 ;
    END
  END out2_2[10]
  PIN out2_2[1]
    DIRECTION OUTPUT ;
    USE SIGNAL ;
    ANTENNADIFFAREA 0.340600 ;
    PORT
      LAYER met3 ;
        RECT 0.000 151.000 4.000 151.600 ;
    END
  END out2_2[1]
  PIN out2_2[2]
    DIRECTION OUTPUT ;
    USE SIGNAL ;
    ANTENNADIFFAREA 0.340600 ;
    PORT
      LAYER met3 ;
        RECT 0.000 152.360 4.000 152.960 ;
    END
  END out2_2[2]
  PIN out2_2[3]
    DIRECTION OUTPUT ;
    USE SIGNAL ;
    ANTENNADIFFAREA 0.340600 ;
    PORT
      LAYER met3 ;
        RECT 0.000 153.720 4.000 154.320 ;
    END
  END out2_2[3]
  PIN out2_2[4]
    DIRECTION OUTPUT ;
    USE SIGNAL ;
    ANTENNADIFFAREA 0.340600 ;
    PORT
      LAYER met3 ;
        RECT 0.000 155.080 4.000 155.680 ;
    END
  END out2_2[4]
  PIN out2_2[5]
    DIRECTION OUTPUT ;
    USE SIGNAL ;
    ANTENNADIFFAREA 0.340600 ;
    PORT
      LAYER met3 ;
        RECT 0.000 156.440 4.000 157.040 ;
    END
  END out2_2[5]
  PIN out2_2[6]
    DIRECTION OUTPUT ;
    USE SIGNAL ;
    ANTENNADIFFAREA 0.340600 ;
    PORT
      LAYER met3 ;
        RECT 0.000 157.800 4.000 158.400 ;
    END
  END out2_2[6]
  PIN out2_2[7]
    DIRECTION OUTPUT ;
    USE SIGNAL ;
    ANTENNADIFFAREA 0.340600 ;
    PORT
      LAYER met3 ;
        RECT 0.000 159.160 4.000 159.760 ;
    END
  END out2_2[7]
  PIN out2_2[8]
    DIRECTION OUTPUT ;
    USE SIGNAL ;
    ANTENNADIFFAREA 0.340600 ;
    PORT
      LAYER met3 ;
        RECT 0.000 160.520 4.000 161.120 ;
    END
  END out2_2[8]
  PIN out2_2[9]
    DIRECTION OUTPUT ;
    USE SIGNAL ;
    ANTENNADIFFAREA 0.340600 ;
    PORT
      LAYER met3 ;
        RECT 0.000 161.880 4.000 162.480 ;
    END
  END out2_2[9]
  PIN out2_3[0]
    DIRECTION OUTPUT ;
    USE SIGNAL ;
    ANTENNADIFFAREA 0.340600 ;
    PORT
      LAYER met3 ;
        RECT 0.000 164.600 4.000 165.200 ;
    END
  END out2_3[0]
  PIN out2_3[10]
    DIRECTION OUTPUT ;
    USE SIGNAL ;
    ANTENNADIFFAREA 0.340600 ;
    PORT
      LAYER met3 ;
        RECT 0.000 178.200 4.000 178.800 ;
    END
  END out2_3[10]
  PIN out2_3[1]
    DIRECTION OUTPUT ;
    USE SIGNAL ;
    ANTENNADIFFAREA 0.340600 ;
    PORT
      LAYER met3 ;
        RECT 0.000 165.960 4.000 166.560 ;
    END
  END out2_3[1]
  PIN out2_3[2]
    DIRECTION OUTPUT ;
    USE SIGNAL ;
    ANTENNADIFFAREA 0.340600 ;
    PORT
      LAYER met3 ;
        RECT 0.000 167.320 4.000 167.920 ;
    END
  END out2_3[2]
  PIN out2_3[3]
    DIRECTION OUTPUT ;
    USE SIGNAL ;
    ANTENNADIFFAREA 0.340600 ;
    PORT
      LAYER met3 ;
        RECT 0.000 168.680 4.000 169.280 ;
    END
  END out2_3[3]
  PIN out2_3[4]
    DIRECTION OUTPUT ;
    USE SIGNAL ;
    ANTENNADIFFAREA 0.340600 ;
    PORT
      LAYER met3 ;
        RECT 0.000 170.040 4.000 170.640 ;
    END
  END out2_3[4]
  PIN out2_3[5]
    DIRECTION OUTPUT ;
    USE SIGNAL ;
    ANTENNADIFFAREA 0.340600 ;
    PORT
      LAYER met3 ;
        RECT 0.000 171.400 4.000 172.000 ;
    END
  END out2_3[5]
  PIN out2_3[6]
    DIRECTION OUTPUT ;
    USE SIGNAL ;
    ANTENNADIFFAREA 0.340600 ;
    PORT
      LAYER met3 ;
        RECT 0.000 172.760 4.000 173.360 ;
    END
  END out2_3[6]
  PIN out2_3[7]
    DIRECTION OUTPUT ;
    USE SIGNAL ;
    ANTENNADIFFAREA 0.340600 ;
    PORT
      LAYER met3 ;
        RECT 0.000 174.120 4.000 174.720 ;
    END
  END out2_3[7]
  PIN out2_3[8]
    DIRECTION OUTPUT ;
    USE SIGNAL ;
    ANTENNADIFFAREA 0.340600 ;
    PORT
      LAYER met3 ;
        RECT 0.000 175.480 4.000 176.080 ;
    END
  END out2_3[8]
  PIN out2_3[9]
    DIRECTION OUTPUT ;
    USE SIGNAL ;
    ANTENNADIFFAREA 0.340600 ;
    PORT
      LAYER met3 ;
        RECT 0.000 176.840 4.000 177.440 ;
    END
  END out2_3[9]
  PIN out2_4[0]
    DIRECTION OUTPUT ;
    USE SIGNAL ;
    ANTENNADIFFAREA 0.340600 ;
    PORT
      LAYER met3 ;
        RECT 0.000 179.560 4.000 180.160 ;
    END
  END out2_4[0]
  PIN out2_4[10]
    DIRECTION OUTPUT ;
    USE SIGNAL ;
    ANTENNADIFFAREA 0.340600 ;
    PORT
      LAYER met3 ;
        RECT 0.000 193.160 4.000 193.760 ;
    END
  END out2_4[10]
  PIN out2_4[1]
    DIRECTION OUTPUT ;
    USE SIGNAL ;
    ANTENNADIFFAREA 0.340600 ;
    PORT
      LAYER met3 ;
        RECT 0.000 180.920 4.000 181.520 ;
    END
  END out2_4[1]
  PIN out2_4[2]
    DIRECTION OUTPUT ;
    USE SIGNAL ;
    ANTENNADIFFAREA 0.340600 ;
    PORT
      LAYER met3 ;
        RECT 0.000 182.280 4.000 182.880 ;
    END
  END out2_4[2]
  PIN out2_4[3]
    DIRECTION OUTPUT ;
    USE SIGNAL ;
    ANTENNADIFFAREA 0.340600 ;
    PORT
      LAYER met3 ;
        RECT 0.000 183.640 4.000 184.240 ;
    END
  END out2_4[3]
  PIN out2_4[4]
    DIRECTION OUTPUT ;
    USE SIGNAL ;
    ANTENNADIFFAREA 0.340600 ;
    PORT
      LAYER met3 ;
        RECT 0.000 185.000 4.000 185.600 ;
    END
  END out2_4[4]
  PIN out2_4[5]
    DIRECTION OUTPUT ;
    USE SIGNAL ;
    ANTENNADIFFAREA 0.340600 ;
    PORT
      LAYER met3 ;
        RECT 0.000 186.360 4.000 186.960 ;
    END
  END out2_4[5]
  PIN out2_4[6]
    DIRECTION OUTPUT ;
    USE SIGNAL ;
    ANTENNADIFFAREA 0.340600 ;
    PORT
      LAYER met3 ;
        RECT 0.000 187.720 4.000 188.320 ;
    END
  END out2_4[6]
  PIN out2_4[7]
    DIRECTION OUTPUT ;
    USE SIGNAL ;
    ANTENNADIFFAREA 0.340600 ;
    PORT
      LAYER met3 ;
        RECT 0.000 189.080 4.000 189.680 ;
    END
  END out2_4[7]
  PIN out2_4[8]
    DIRECTION OUTPUT ;
    USE SIGNAL ;
    ANTENNADIFFAREA 0.340600 ;
    PORT
      LAYER met3 ;
        RECT 0.000 190.440 4.000 191.040 ;
    END
  END out2_4[8]
  PIN out2_4[9]
    DIRECTION OUTPUT ;
    USE SIGNAL ;
    ANTENNADIFFAREA 0.340600 ;
    PORT
      LAYER met3 ;
        RECT 0.000 191.800 4.000 192.400 ;
    END
  END out2_4[9]
  PIN out2_5[0]
    DIRECTION OUTPUT ;
    USE SIGNAL ;
    ANTENNADIFFAREA 0.340600 ;
    PORT
      LAYER met3 ;
        RECT 0.000 194.520 4.000 195.120 ;
    END
  END out2_5[0]
  PIN out2_5[10]
    DIRECTION OUTPUT ;
    USE SIGNAL ;
    ANTENNADIFFAREA 0.340600 ;
    PORT
      LAYER met3 ;
        RECT 0.000 208.120 4.000 208.720 ;
    END
  END out2_5[10]
  PIN out2_5[1]
    DIRECTION OUTPUT ;
    USE SIGNAL ;
    ANTENNADIFFAREA 0.340600 ;
    PORT
      LAYER met3 ;
        RECT 0.000 195.880 4.000 196.480 ;
    END
  END out2_5[1]
  PIN out2_5[2]
    DIRECTION OUTPUT ;
    USE SIGNAL ;
    ANTENNADIFFAREA 0.340600 ;
    PORT
      LAYER met3 ;
        RECT 0.000 197.240 4.000 197.840 ;
    END
  END out2_5[2]
  PIN out2_5[3]
    DIRECTION OUTPUT ;
    USE SIGNAL ;
    ANTENNADIFFAREA 0.340600 ;
    PORT
      LAYER met3 ;
        RECT 0.000 198.600 4.000 199.200 ;
    END
  END out2_5[3]
  PIN out2_5[4]
    DIRECTION OUTPUT ;
    USE SIGNAL ;
    ANTENNADIFFAREA 0.340600 ;
    PORT
      LAYER met3 ;
        RECT 0.000 199.960 4.000 200.560 ;
    END
  END out2_5[4]
  PIN out2_5[5]
    DIRECTION OUTPUT ;
    USE SIGNAL ;
    ANTENNADIFFAREA 0.340600 ;
    PORT
      LAYER met3 ;
        RECT 0.000 201.320 4.000 201.920 ;
    END
  END out2_5[5]
  PIN out2_5[6]
    DIRECTION OUTPUT ;
    USE SIGNAL ;
    ANTENNADIFFAREA 0.340600 ;
    PORT
      LAYER met3 ;
        RECT 0.000 202.680 4.000 203.280 ;
    END
  END out2_5[6]
  PIN out2_5[7]
    DIRECTION OUTPUT ;
    USE SIGNAL ;
    ANTENNADIFFAREA 0.340600 ;
    PORT
      LAYER met3 ;
        RECT 0.000 204.040 4.000 204.640 ;
    END
  END out2_5[7]
  PIN out2_5[8]
    DIRECTION OUTPUT ;
    USE SIGNAL ;
    ANTENNADIFFAREA 0.340600 ;
    PORT
      LAYER met3 ;
        RECT 0.000 205.400 4.000 206.000 ;
    END
  END out2_5[8]
  PIN out2_5[9]
    DIRECTION OUTPUT ;
    USE SIGNAL ;
    ANTENNADIFFAREA 0.340600 ;
    PORT
      LAYER met3 ;
        RECT 0.000 206.760 4.000 207.360 ;
    END
  END out2_5[9]
  PIN out2_6[0]
    DIRECTION OUTPUT ;
    USE SIGNAL ;
    ANTENNADIFFAREA 0.340600 ;
    PORT
      LAYER met3 ;
        RECT 0.000 209.480 4.000 210.080 ;
    END
  END out2_6[0]
  PIN out2_6[10]
    DIRECTION OUTPUT ;
    USE SIGNAL ;
    ANTENNADIFFAREA 0.340600 ;
    PORT
      LAYER met3 ;
        RECT 0.000 223.080 4.000 223.680 ;
    END
  END out2_6[10]
  PIN out2_6[1]
    DIRECTION OUTPUT ;
    USE SIGNAL ;
    ANTENNADIFFAREA 0.340600 ;
    PORT
      LAYER met3 ;
        RECT 0.000 210.840 4.000 211.440 ;
    END
  END out2_6[1]
  PIN out2_6[2]
    DIRECTION OUTPUT ;
    USE SIGNAL ;
    ANTENNADIFFAREA 0.340600 ;
    PORT
      LAYER met3 ;
        RECT 0.000 212.200 4.000 212.800 ;
    END
  END out2_6[2]
  PIN out2_6[3]
    DIRECTION OUTPUT ;
    USE SIGNAL ;
    ANTENNADIFFAREA 0.340600 ;
    PORT
      LAYER met3 ;
        RECT 0.000 213.560 4.000 214.160 ;
    END
  END out2_6[3]
  PIN out2_6[4]
    DIRECTION OUTPUT ;
    USE SIGNAL ;
    ANTENNADIFFAREA 0.340600 ;
    PORT
      LAYER met3 ;
        RECT 0.000 214.920 4.000 215.520 ;
    END
  END out2_6[4]
  PIN out2_6[5]
    DIRECTION OUTPUT ;
    USE SIGNAL ;
    ANTENNADIFFAREA 0.340600 ;
    PORT
      LAYER met3 ;
        RECT 0.000 216.280 4.000 216.880 ;
    END
  END out2_6[5]
  PIN out2_6[6]
    DIRECTION OUTPUT ;
    USE SIGNAL ;
    ANTENNADIFFAREA 0.340600 ;
    PORT
      LAYER met3 ;
        RECT 0.000 217.640 4.000 218.240 ;
    END
  END out2_6[6]
  PIN out2_6[7]
    DIRECTION OUTPUT ;
    USE SIGNAL ;
    ANTENNADIFFAREA 0.340600 ;
    PORT
      LAYER met3 ;
        RECT 0.000 219.000 4.000 219.600 ;
    END
  END out2_6[7]
  PIN out2_6[8]
    DIRECTION OUTPUT ;
    USE SIGNAL ;
    ANTENNADIFFAREA 0.340600 ;
    PORT
      LAYER met3 ;
        RECT 0.000 220.360 4.000 220.960 ;
    END
  END out2_6[8]
  PIN out2_6[9]
    DIRECTION OUTPUT ;
    USE SIGNAL ;
    ANTENNADIFFAREA 0.340600 ;
    PORT
      LAYER met3 ;
        RECT 0.000 221.720 4.000 222.320 ;
    END
  END out2_6[9]
  PIN out2_7[0]
    DIRECTION OUTPUT ;
    USE SIGNAL ;
    ANTENNADIFFAREA 0.340600 ;
    PORT
      LAYER met3 ;
        RECT 0.000 224.440 4.000 225.040 ;
    END
  END out2_7[0]
  PIN out2_7[10]
    DIRECTION OUTPUT ;
    USE SIGNAL ;
    ANTENNADIFFAREA 0.340600 ;
    PORT
      LAYER met3 ;
        RECT 0.000 238.040 4.000 238.640 ;
    END
  END out2_7[10]
  PIN out2_7[1]
    DIRECTION OUTPUT ;
    USE SIGNAL ;
    ANTENNADIFFAREA 0.340600 ;
    PORT
      LAYER met3 ;
        RECT 0.000 225.800 4.000 226.400 ;
    END
  END out2_7[1]
  PIN out2_7[2]
    DIRECTION OUTPUT ;
    USE SIGNAL ;
    ANTENNADIFFAREA 0.340600 ;
    PORT
      LAYER met3 ;
        RECT 0.000 227.160 4.000 227.760 ;
    END
  END out2_7[2]
  PIN out2_7[3]
    DIRECTION OUTPUT ;
    USE SIGNAL ;
    ANTENNADIFFAREA 0.340600 ;
    PORT
      LAYER met3 ;
        RECT 0.000 228.520 4.000 229.120 ;
    END
  END out2_7[3]
  PIN out2_7[4]
    DIRECTION OUTPUT ;
    USE SIGNAL ;
    ANTENNADIFFAREA 0.340600 ;
    PORT
      LAYER met3 ;
        RECT 0.000 229.880 4.000 230.480 ;
    END
  END out2_7[4]
  PIN out2_7[5]
    DIRECTION OUTPUT ;
    USE SIGNAL ;
    ANTENNADIFFAREA 0.340600 ;
    PORT
      LAYER met3 ;
        RECT 0.000 231.240 4.000 231.840 ;
    END
  END out2_7[5]
  PIN out2_7[6]
    DIRECTION OUTPUT ;
    USE SIGNAL ;
    ANTENNADIFFAREA 0.340600 ;
    PORT
      LAYER met3 ;
        RECT 0.000 232.600 4.000 233.200 ;
    END
  END out2_7[6]
  PIN out2_7[7]
    DIRECTION OUTPUT ;
    USE SIGNAL ;
    ANTENNADIFFAREA 0.340600 ;
    PORT
      LAYER met3 ;
        RECT 0.000 233.960 4.000 234.560 ;
    END
  END out2_7[7]
  PIN out2_7[8]
    DIRECTION OUTPUT ;
    USE SIGNAL ;
    ANTENNADIFFAREA 0.340600 ;
    PORT
      LAYER met3 ;
        RECT 0.000 235.320 4.000 235.920 ;
    END
  END out2_7[8]
  PIN out2_7[9]
    DIRECTION OUTPUT ;
    USE SIGNAL ;
    ANTENNADIFFAREA 0.340600 ;
    PORT
      LAYER met3 ;
        RECT 0.000 236.680 4.000 237.280 ;
    END
  END out2_7[9]
  PIN out2_8[0]
    DIRECTION OUTPUT ;
    USE SIGNAL ;
    ANTENNADIFFAREA 0.340600 ;
    PORT
      LAYER met3 ;
        RECT 0.000 239.400 4.000 240.000 ;
    END
  END out2_8[0]
  PIN out2_8[10]
    DIRECTION OUTPUT ;
    USE SIGNAL ;
    ANTENNADIFFAREA 0.340600 ;
    PORT
      LAYER met3 ;
        RECT 0.000 253.000 4.000 253.600 ;
    END
  END out2_8[10]
  PIN out2_8[1]
    DIRECTION OUTPUT ;
    USE SIGNAL ;
    ANTENNADIFFAREA 0.340600 ;
    PORT
      LAYER met3 ;
        RECT 0.000 240.760 4.000 241.360 ;
    END
  END out2_8[1]
  PIN out2_8[2]
    DIRECTION OUTPUT ;
    USE SIGNAL ;
    ANTENNADIFFAREA 0.340600 ;
    PORT
      LAYER met3 ;
        RECT 0.000 242.120 4.000 242.720 ;
    END
  END out2_8[2]
  PIN out2_8[3]
    DIRECTION OUTPUT ;
    USE SIGNAL ;
    ANTENNADIFFAREA 0.340600 ;
    PORT
      LAYER met3 ;
        RECT 0.000 243.480 4.000 244.080 ;
    END
  END out2_8[3]
  PIN out2_8[4]
    DIRECTION OUTPUT ;
    USE SIGNAL ;
    ANTENNADIFFAREA 0.340600 ;
    PORT
      LAYER met3 ;
        RECT 0.000 244.840 4.000 245.440 ;
    END
  END out2_8[4]
  PIN out2_8[5]
    DIRECTION OUTPUT ;
    USE SIGNAL ;
    ANTENNADIFFAREA 0.340600 ;
    PORT
      LAYER met3 ;
        RECT 0.000 246.200 4.000 246.800 ;
    END
  END out2_8[5]
  PIN out2_8[6]
    DIRECTION OUTPUT ;
    USE SIGNAL ;
    ANTENNADIFFAREA 0.340600 ;
    PORT
      LAYER met3 ;
        RECT 0.000 247.560 4.000 248.160 ;
    END
  END out2_8[6]
  PIN out2_8[7]
    DIRECTION OUTPUT ;
    USE SIGNAL ;
    ANTENNADIFFAREA 0.340600 ;
    PORT
      LAYER met3 ;
        RECT 0.000 248.920 4.000 249.520 ;
    END
  END out2_8[7]
  PIN out2_8[8]
    DIRECTION OUTPUT ;
    USE SIGNAL ;
    ANTENNADIFFAREA 0.340600 ;
    PORT
      LAYER met3 ;
        RECT 0.000 250.280 4.000 250.880 ;
    END
  END out2_8[8]
  PIN out2_8[9]
    DIRECTION OUTPUT ;
    USE SIGNAL ;
    ANTENNADIFFAREA 0.340600 ;
    PORT
      LAYER met3 ;
        RECT 0.000 251.640 4.000 252.240 ;
    END
  END out2_8[9]
  PIN partial_sum14[0]
    DIRECTION OUTPUT ;
    USE SIGNAL ;
    ANTENNADIFFAREA 0.340600 ;
    PORT
      LAYER met2 ;
        RECT 151.890 0.000 152.170 4.000 ;
    END
  END partial_sum14[0]
  PIN partial_sum14[10]
    DIRECTION OUTPUT ;
    USE SIGNAL ;
    ANTENNADIFFAREA 0.340600 ;
    PORT
      LAYER met2 ;
        RECT 165.690 0.000 165.970 4.000 ;
    END
  END partial_sum14[10]
  PIN partial_sum14[11]
    DIRECTION OUTPUT ;
    USE SIGNAL ;
    ANTENNADIFFAREA 0.340600 ;
    PORT
      LAYER met2 ;
        RECT 167.070 0.000 167.350 4.000 ;
    END
  END partial_sum14[11]
  PIN partial_sum14[12]
    DIRECTION OUTPUT ;
    USE SIGNAL ;
    ANTENNADIFFAREA 0.340600 ;
    PORT
      LAYER met2 ;
        RECT 168.450 0.000 168.730 4.000 ;
    END
  END partial_sum14[12]
  PIN partial_sum14[13]
    DIRECTION OUTPUT ;
    USE SIGNAL ;
    ANTENNADIFFAREA 0.340600 ;
    PORT
      LAYER met2 ;
        RECT 169.830 0.000 170.110 4.000 ;
    END
  END partial_sum14[13]
  PIN partial_sum14[1]
    DIRECTION OUTPUT ;
    USE SIGNAL ;
    ANTENNADIFFAREA 0.340600 ;
    PORT
      LAYER met2 ;
        RECT 153.270 0.000 153.550 4.000 ;
    END
  END partial_sum14[1]
  PIN partial_sum14[2]
    DIRECTION OUTPUT ;
    USE SIGNAL ;
    ANTENNADIFFAREA 0.340600 ;
    PORT
      LAYER met2 ;
        RECT 154.650 0.000 154.930 4.000 ;
    END
  END partial_sum14[2]
  PIN partial_sum14[3]
    DIRECTION OUTPUT ;
    USE SIGNAL ;
    ANTENNADIFFAREA 0.340600 ;
    PORT
      LAYER met2 ;
        RECT 156.030 0.000 156.310 4.000 ;
    END
  END partial_sum14[3]
  PIN partial_sum14[4]
    DIRECTION OUTPUT ;
    USE SIGNAL ;
    ANTENNADIFFAREA 0.340600 ;
    PORT
      LAYER met2 ;
        RECT 157.410 0.000 157.690 4.000 ;
    END
  END partial_sum14[4]
  PIN partial_sum14[5]
    DIRECTION OUTPUT ;
    USE SIGNAL ;
    ANTENNADIFFAREA 0.340600 ;
    PORT
      LAYER met2 ;
        RECT 158.790 0.000 159.070 4.000 ;
    END
  END partial_sum14[5]
  PIN partial_sum14[6]
    DIRECTION OUTPUT ;
    USE SIGNAL ;
    ANTENNADIFFAREA 0.340600 ;
    PORT
      LAYER met2 ;
        RECT 160.170 0.000 160.450 4.000 ;
    END
  END partial_sum14[6]
  PIN partial_sum14[7]
    DIRECTION OUTPUT ;
    USE SIGNAL ;
    ANTENNADIFFAREA 0.340600 ;
    PORT
      LAYER met2 ;
        RECT 161.550 0.000 161.830 4.000 ;
    END
  END partial_sum14[7]
  PIN partial_sum14[8]
    DIRECTION OUTPUT ;
    USE SIGNAL ;
    ANTENNADIFFAREA 0.340600 ;
    PORT
      LAYER met2 ;
        RECT 162.930 0.000 163.210 4.000 ;
    END
  END partial_sum14[8]
  PIN partial_sum14[9]
    DIRECTION OUTPUT ;
    USE SIGNAL ;
    ANTENNADIFFAREA 0.340600 ;
    PORT
      LAYER met2 ;
        RECT 164.310 0.000 164.590 4.000 ;
    END
  END partial_sum14[9]
  PIN partial_sum14_1[0]
    DIRECTION OUTPUT ;
    USE SIGNAL ;
    ANTENNADIFFAREA 0.340600 ;
    PORT
      LAYER met2 ;
        RECT 171.210 0.000 171.490 4.000 ;
    END
  END partial_sum14_1[0]
  PIN partial_sum14_1[10]
    DIRECTION OUTPUT ;
    USE SIGNAL ;
    ANTENNADIFFAREA 0.340600 ;
    PORT
      LAYER met2 ;
        RECT 185.010 0.000 185.290 4.000 ;
    END
  END partial_sum14_1[10]
  PIN partial_sum14_1[11]
    DIRECTION OUTPUT ;
    USE SIGNAL ;
    ANTENNADIFFAREA 0.340600 ;
    PORT
      LAYER met2 ;
        RECT 186.390 0.000 186.670 4.000 ;
    END
  END partial_sum14_1[11]
  PIN partial_sum14_1[12]
    DIRECTION OUTPUT ;
    USE SIGNAL ;
    ANTENNADIFFAREA 0.340600 ;
    PORT
      LAYER met2 ;
        RECT 187.770 0.000 188.050 4.000 ;
    END
  END partial_sum14_1[12]
  PIN partial_sum14_1[13]
    DIRECTION OUTPUT ;
    USE SIGNAL ;
    ANTENNADIFFAREA 0.340600 ;
    PORT
      LAYER met2 ;
        RECT 189.150 0.000 189.430 4.000 ;
    END
  END partial_sum14_1[13]
  PIN partial_sum14_1[1]
    DIRECTION OUTPUT ;
    USE SIGNAL ;
    ANTENNADIFFAREA 0.340600 ;
    PORT
      LAYER met2 ;
        RECT 172.590 0.000 172.870 4.000 ;
    END
  END partial_sum14_1[1]
  PIN partial_sum14_1[2]
    DIRECTION OUTPUT ;
    USE SIGNAL ;
    ANTENNADIFFAREA 0.340600 ;
    PORT
      LAYER met2 ;
        RECT 173.970 0.000 174.250 4.000 ;
    END
  END partial_sum14_1[2]
  PIN partial_sum14_1[3]
    DIRECTION OUTPUT ;
    USE SIGNAL ;
    ANTENNADIFFAREA 0.340600 ;
    PORT
      LAYER met2 ;
        RECT 175.350 0.000 175.630 4.000 ;
    END
  END partial_sum14_1[3]
  PIN partial_sum14_1[4]
    DIRECTION OUTPUT ;
    USE SIGNAL ;
    ANTENNADIFFAREA 0.340600 ;
    PORT
      LAYER met2 ;
        RECT 176.730 0.000 177.010 4.000 ;
    END
  END partial_sum14_1[4]
  PIN partial_sum14_1[5]
    DIRECTION OUTPUT ;
    USE SIGNAL ;
    ANTENNADIFFAREA 0.340600 ;
    PORT
      LAYER met2 ;
        RECT 178.110 0.000 178.390 4.000 ;
    END
  END partial_sum14_1[5]
  PIN partial_sum14_1[6]
    DIRECTION OUTPUT ;
    USE SIGNAL ;
    ANTENNADIFFAREA 0.340600 ;
    PORT
      LAYER met2 ;
        RECT 179.490 0.000 179.770 4.000 ;
    END
  END partial_sum14_1[6]
  PIN partial_sum14_1[7]
    DIRECTION OUTPUT ;
    USE SIGNAL ;
    ANTENNADIFFAREA 0.340600 ;
    PORT
      LAYER met2 ;
        RECT 180.870 0.000 181.150 4.000 ;
    END
  END partial_sum14_1[7]
  PIN partial_sum14_1[8]
    DIRECTION OUTPUT ;
    USE SIGNAL ;
    ANTENNADIFFAREA 0.340600 ;
    PORT
      LAYER met2 ;
        RECT 182.250 0.000 182.530 4.000 ;
    END
  END partial_sum14_1[8]
  PIN partial_sum14_1[9]
    DIRECTION OUTPUT ;
    USE SIGNAL ;
    ANTENNADIFFAREA 0.340600 ;
    PORT
      LAYER met2 ;
        RECT 183.630 0.000 183.910 4.000 ;
    END
  END partial_sum14_1[9]
  PIN partial_sum14_2[0]
    DIRECTION OUTPUT ;
    USE SIGNAL ;
    ANTENNADIFFAREA 0.340600 ;
    PORT
      LAYER met2 ;
        RECT 190.530 0.000 190.810 4.000 ;
    END
  END partial_sum14_2[0]
  PIN partial_sum14_2[10]
    DIRECTION OUTPUT ;
    USE SIGNAL ;
    ANTENNADIFFAREA 0.340600 ;
    PORT
      LAYER met2 ;
        RECT 204.330 0.000 204.610 4.000 ;
    END
  END partial_sum14_2[10]
  PIN partial_sum14_2[11]
    DIRECTION OUTPUT ;
    USE SIGNAL ;
    ANTENNADIFFAREA 0.340600 ;
    PORT
      LAYER met2 ;
        RECT 205.710 0.000 205.990 4.000 ;
    END
  END partial_sum14_2[11]
  PIN partial_sum14_2[12]
    DIRECTION OUTPUT ;
    USE SIGNAL ;
    ANTENNADIFFAREA 0.340600 ;
    PORT
      LAYER met2 ;
        RECT 207.090 0.000 207.370 4.000 ;
    END
  END partial_sum14_2[12]
  PIN partial_sum14_2[13]
    DIRECTION OUTPUT ;
    USE SIGNAL ;
    ANTENNADIFFAREA 0.340600 ;
    PORT
      LAYER met2 ;
        RECT 208.470 0.000 208.750 4.000 ;
    END
  END partial_sum14_2[13]
  PIN partial_sum14_2[1]
    DIRECTION OUTPUT ;
    USE SIGNAL ;
    ANTENNADIFFAREA 0.340600 ;
    PORT
      LAYER met2 ;
        RECT 191.910 0.000 192.190 4.000 ;
    END
  END partial_sum14_2[1]
  PIN partial_sum14_2[2]
    DIRECTION OUTPUT ;
    USE SIGNAL ;
    ANTENNADIFFAREA 0.340600 ;
    PORT
      LAYER met2 ;
        RECT 193.290 0.000 193.570 4.000 ;
    END
  END partial_sum14_2[2]
  PIN partial_sum14_2[3]
    DIRECTION OUTPUT ;
    USE SIGNAL ;
    ANTENNADIFFAREA 0.340600 ;
    PORT
      LAYER met2 ;
        RECT 194.670 0.000 194.950 4.000 ;
    END
  END partial_sum14_2[3]
  PIN partial_sum14_2[4]
    DIRECTION OUTPUT ;
    USE SIGNAL ;
    ANTENNADIFFAREA 0.340600 ;
    PORT
      LAYER met2 ;
        RECT 196.050 0.000 196.330 4.000 ;
    END
  END partial_sum14_2[4]
  PIN partial_sum14_2[5]
    DIRECTION OUTPUT ;
    USE SIGNAL ;
    ANTENNADIFFAREA 0.340600 ;
    PORT
      LAYER met2 ;
        RECT 197.430 0.000 197.710 4.000 ;
    END
  END partial_sum14_2[5]
  PIN partial_sum14_2[6]
    DIRECTION OUTPUT ;
    USE SIGNAL ;
    ANTENNADIFFAREA 0.340600 ;
    PORT
      LAYER met2 ;
        RECT 198.810 0.000 199.090 4.000 ;
    END
  END partial_sum14_2[6]
  PIN partial_sum14_2[7]
    DIRECTION OUTPUT ;
    USE SIGNAL ;
    ANTENNADIFFAREA 0.340600 ;
    PORT
      LAYER met2 ;
        RECT 200.190 0.000 200.470 4.000 ;
    END
  END partial_sum14_2[7]
  PIN partial_sum14_2[8]
    DIRECTION OUTPUT ;
    USE SIGNAL ;
    ANTENNADIFFAREA 0.340600 ;
    PORT
      LAYER met2 ;
        RECT 201.570 0.000 201.850 4.000 ;
    END
  END partial_sum14_2[8]
  PIN partial_sum14_2[9]
    DIRECTION OUTPUT ;
    USE SIGNAL ;
    ANTENNADIFFAREA 0.340600 ;
    PORT
      LAYER met2 ;
        RECT 202.950 0.000 203.230 4.000 ;
    END
  END partial_sum14_2[9]
  PIN partial_sum14_3[0]
    DIRECTION OUTPUT ;
    USE SIGNAL ;
    ANTENNADIFFAREA 0.340600 ;
    PORT
      LAYER met2 ;
        RECT 209.850 0.000 210.130 4.000 ;
    END
  END partial_sum14_3[0]
  PIN partial_sum14_3[10]
    DIRECTION OUTPUT ;
    USE SIGNAL ;
    ANTENNADIFFAREA 0.340600 ;
    PORT
      LAYER met2 ;
        RECT 223.650 0.000 223.930 4.000 ;
    END
  END partial_sum14_3[10]
  PIN partial_sum14_3[11]
    DIRECTION OUTPUT ;
    USE SIGNAL ;
    ANTENNADIFFAREA 0.340600 ;
    PORT
      LAYER met2 ;
        RECT 225.030 0.000 225.310 4.000 ;
    END
  END partial_sum14_3[11]
  PIN partial_sum14_3[12]
    DIRECTION OUTPUT ;
    USE SIGNAL ;
    ANTENNADIFFAREA 0.340600 ;
    PORT
      LAYER met2 ;
        RECT 226.410 0.000 226.690 4.000 ;
    END
  END partial_sum14_3[12]
  PIN partial_sum14_3[13]
    DIRECTION OUTPUT ;
    USE SIGNAL ;
    ANTENNADIFFAREA 0.340600 ;
    PORT
      LAYER met2 ;
        RECT 227.790 0.000 228.070 4.000 ;
    END
  END partial_sum14_3[13]
  PIN partial_sum14_3[1]
    DIRECTION OUTPUT ;
    USE SIGNAL ;
    ANTENNADIFFAREA 0.340600 ;
    PORT
      LAYER met2 ;
        RECT 211.230 0.000 211.510 4.000 ;
    END
  END partial_sum14_3[1]
  PIN partial_sum14_3[2]
    DIRECTION OUTPUT ;
    USE SIGNAL ;
    ANTENNADIFFAREA 0.340600 ;
    PORT
      LAYER met2 ;
        RECT 212.610 0.000 212.890 4.000 ;
    END
  END partial_sum14_3[2]
  PIN partial_sum14_3[3]
    DIRECTION OUTPUT ;
    USE SIGNAL ;
    ANTENNADIFFAREA 0.340600 ;
    PORT
      LAYER met2 ;
        RECT 213.990 0.000 214.270 4.000 ;
    END
  END partial_sum14_3[3]
  PIN partial_sum14_3[4]
    DIRECTION OUTPUT ;
    USE SIGNAL ;
    ANTENNADIFFAREA 0.340600 ;
    PORT
      LAYER met2 ;
        RECT 215.370 0.000 215.650 4.000 ;
    END
  END partial_sum14_3[4]
  PIN partial_sum14_3[5]
    DIRECTION OUTPUT ;
    USE SIGNAL ;
    ANTENNADIFFAREA 0.340600 ;
    PORT
      LAYER met2 ;
        RECT 216.750 0.000 217.030 4.000 ;
    END
  END partial_sum14_3[5]
  PIN partial_sum14_3[6]
    DIRECTION OUTPUT ;
    USE SIGNAL ;
    ANTENNADIFFAREA 0.340600 ;
    PORT
      LAYER met2 ;
        RECT 218.130 0.000 218.410 4.000 ;
    END
  END partial_sum14_3[6]
  PIN partial_sum14_3[7]
    DIRECTION OUTPUT ;
    USE SIGNAL ;
    ANTENNADIFFAREA 0.340600 ;
    PORT
      LAYER met2 ;
        RECT 219.510 0.000 219.790 4.000 ;
    END
  END partial_sum14_3[7]
  PIN partial_sum14_3[8]
    DIRECTION OUTPUT ;
    USE SIGNAL ;
    ANTENNADIFFAREA 0.340600 ;
    PORT
      LAYER met2 ;
        RECT 220.890 0.000 221.170 4.000 ;
    END
  END partial_sum14_3[8]
  PIN partial_sum14_3[9]
    DIRECTION OUTPUT ;
    USE SIGNAL ;
    ANTENNADIFFAREA 0.340600 ;
    PORT
      LAYER met2 ;
        RECT 222.270 0.000 222.550 4.000 ;
    END
  END partial_sum14_3[9]
  PIN partial_sum15[0]
    DIRECTION OUTPUT ;
    USE SIGNAL ;
    ANTENNADIFFAREA 0.340600 ;
    PORT
      LAYER met2 ;
        RECT 229.170 0.000 229.450 4.000 ;
    END
  END partial_sum15[0]
  PIN partial_sum15[10]
    DIRECTION OUTPUT ;
    USE SIGNAL ;
    ANTENNADIFFAREA 0.340600 ;
    PORT
      LAYER met2 ;
        RECT 242.970 0.000 243.250 4.000 ;
    END
  END partial_sum15[10]
  PIN partial_sum15[11]
    DIRECTION OUTPUT ;
    USE SIGNAL ;
    ANTENNADIFFAREA 0.340600 ;
    PORT
      LAYER met2 ;
        RECT 244.350 0.000 244.630 4.000 ;
    END
  END partial_sum15[11]
  PIN partial_sum15[12]
    DIRECTION OUTPUT ;
    USE SIGNAL ;
    ANTENNADIFFAREA 0.340600 ;
    PORT
      LAYER met2 ;
        RECT 245.730 0.000 246.010 4.000 ;
    END
  END partial_sum15[12]
  PIN partial_sum15[13]
    DIRECTION OUTPUT ;
    USE SIGNAL ;
    ANTENNADIFFAREA 0.340600 ;
    PORT
      LAYER met2 ;
        RECT 247.110 0.000 247.390 4.000 ;
    END
  END partial_sum15[13]
  PIN partial_sum15[14]
    DIRECTION OUTPUT ;
    USE SIGNAL ;
    ANTENNADIFFAREA 0.340600 ;
    PORT
      LAYER met2 ;
        RECT 248.490 0.000 248.770 4.000 ;
    END
  END partial_sum15[14]
  PIN partial_sum15[1]
    DIRECTION OUTPUT ;
    USE SIGNAL ;
    ANTENNADIFFAREA 0.340600 ;
    PORT
      LAYER met2 ;
        RECT 230.550 0.000 230.830 4.000 ;
    END
  END partial_sum15[1]
  PIN partial_sum15[2]
    DIRECTION OUTPUT ;
    USE SIGNAL ;
    ANTENNADIFFAREA 0.340600 ;
    PORT
      LAYER met2 ;
        RECT 231.930 0.000 232.210 4.000 ;
    END
  END partial_sum15[2]
  PIN partial_sum15[3]
    DIRECTION OUTPUT ;
    USE SIGNAL ;
    ANTENNADIFFAREA 0.340600 ;
    PORT
      LAYER met2 ;
        RECT 233.310 0.000 233.590 4.000 ;
    END
  END partial_sum15[3]
  PIN partial_sum15[4]
    DIRECTION OUTPUT ;
    USE SIGNAL ;
    ANTENNADIFFAREA 0.340600 ;
    PORT
      LAYER met2 ;
        RECT 234.690 0.000 234.970 4.000 ;
    END
  END partial_sum15[4]
  PIN partial_sum15[5]
    DIRECTION OUTPUT ;
    USE SIGNAL ;
    ANTENNADIFFAREA 0.340600 ;
    PORT
      LAYER met2 ;
        RECT 236.070 0.000 236.350 4.000 ;
    END
  END partial_sum15[5]
  PIN partial_sum15[6]
    DIRECTION OUTPUT ;
    USE SIGNAL ;
    ANTENNADIFFAREA 0.340600 ;
    PORT
      LAYER met2 ;
        RECT 237.450 0.000 237.730 4.000 ;
    END
  END partial_sum15[6]
  PIN partial_sum15[7]
    DIRECTION OUTPUT ;
    USE SIGNAL ;
    ANTENNADIFFAREA 0.340600 ;
    PORT
      LAYER met2 ;
        RECT 238.830 0.000 239.110 4.000 ;
    END
  END partial_sum15[7]
  PIN partial_sum15[8]
    DIRECTION OUTPUT ;
    USE SIGNAL ;
    ANTENNADIFFAREA 0.340600 ;
    PORT
      LAYER met2 ;
        RECT 240.210 0.000 240.490 4.000 ;
    END
  END partial_sum15[8]
  PIN partial_sum15[9]
    DIRECTION OUTPUT ;
    USE SIGNAL ;
    ANTENNADIFFAREA 0.340600 ;
    PORT
      LAYER met2 ;
        RECT 241.590 0.000 241.870 4.000 ;
    END
  END partial_sum15[9]
  PIN partial_sum15_1[0]
    DIRECTION OUTPUT ;
    USE SIGNAL ;
    ANTENNADIFFAREA 0.340600 ;
    PORT
      LAYER met2 ;
        RECT 249.870 0.000 250.150 4.000 ;
    END
  END partial_sum15_1[0]
  PIN partial_sum15_1[10]
    DIRECTION OUTPUT ;
    USE SIGNAL ;
    ANTENNADIFFAREA 0.340600 ;
    PORT
      LAYER met2 ;
        RECT 263.670 0.000 263.950 4.000 ;
    END
  END partial_sum15_1[10]
  PIN partial_sum15_1[11]
    DIRECTION OUTPUT ;
    USE SIGNAL ;
    ANTENNADIFFAREA 0.340600 ;
    PORT
      LAYER met2 ;
        RECT 265.050 0.000 265.330 4.000 ;
    END
  END partial_sum15_1[11]
  PIN partial_sum15_1[12]
    DIRECTION OUTPUT ;
    USE SIGNAL ;
    ANTENNADIFFAREA 0.340600 ;
    PORT
      LAYER met2 ;
        RECT 266.430 0.000 266.710 4.000 ;
    END
  END partial_sum15_1[12]
  PIN partial_sum15_1[13]
    DIRECTION OUTPUT ;
    USE SIGNAL ;
    ANTENNADIFFAREA 0.340600 ;
    PORT
      LAYER met2 ;
        RECT 267.810 0.000 268.090 4.000 ;
    END
  END partial_sum15_1[13]
  PIN partial_sum15_1[14]
    DIRECTION OUTPUT ;
    USE SIGNAL ;
    ANTENNADIFFAREA 0.340600 ;
    PORT
      LAYER met2 ;
        RECT 269.190 0.000 269.470 4.000 ;
    END
  END partial_sum15_1[14]
  PIN partial_sum15_1[1]
    DIRECTION OUTPUT ;
    USE SIGNAL ;
    ANTENNADIFFAREA 0.340600 ;
    PORT
      LAYER met2 ;
        RECT 251.250 0.000 251.530 4.000 ;
    END
  END partial_sum15_1[1]
  PIN partial_sum15_1[2]
    DIRECTION OUTPUT ;
    USE SIGNAL ;
    ANTENNADIFFAREA 0.340600 ;
    PORT
      LAYER met2 ;
        RECT 252.630 0.000 252.910 4.000 ;
    END
  END partial_sum15_1[2]
  PIN partial_sum15_1[3]
    DIRECTION OUTPUT ;
    USE SIGNAL ;
    ANTENNADIFFAREA 0.340600 ;
    PORT
      LAYER met2 ;
        RECT 254.010 0.000 254.290 4.000 ;
    END
  END partial_sum15_1[3]
  PIN partial_sum15_1[4]
    DIRECTION OUTPUT ;
    USE SIGNAL ;
    ANTENNADIFFAREA 0.340600 ;
    PORT
      LAYER met2 ;
        RECT 255.390 0.000 255.670 4.000 ;
    END
  END partial_sum15_1[4]
  PIN partial_sum15_1[5]
    DIRECTION OUTPUT ;
    USE SIGNAL ;
    ANTENNADIFFAREA 0.340600 ;
    PORT
      LAYER met2 ;
        RECT 256.770 0.000 257.050 4.000 ;
    END
  END partial_sum15_1[5]
  PIN partial_sum15_1[6]
    DIRECTION OUTPUT ;
    USE SIGNAL ;
    ANTENNADIFFAREA 0.340600 ;
    PORT
      LAYER met2 ;
        RECT 258.150 0.000 258.430 4.000 ;
    END
  END partial_sum15_1[6]
  PIN partial_sum15_1[7]
    DIRECTION OUTPUT ;
    USE SIGNAL ;
    ANTENNADIFFAREA 0.340600 ;
    PORT
      LAYER met2 ;
        RECT 259.530 0.000 259.810 4.000 ;
    END
  END partial_sum15_1[7]
  PIN partial_sum15_1[8]
    DIRECTION OUTPUT ;
    USE SIGNAL ;
    ANTENNADIFFAREA 0.340600 ;
    PORT
      LAYER met2 ;
        RECT 260.910 0.000 261.190 4.000 ;
    END
  END partial_sum15_1[8]
  PIN partial_sum15_1[9]
    DIRECTION OUTPUT ;
    USE SIGNAL ;
    ANTENNADIFFAREA 0.340600 ;
    PORT
      LAYER met2 ;
        RECT 262.290 0.000 262.570 4.000 ;
    END
  END partial_sum15_1[9]
  PIN partial_sum16[0]
    DIRECTION OUTPUT ;
    USE SIGNAL ;
    ANTENNADIFFAREA 0.340600 ;
    PORT
      LAYER met2 ;
        RECT 270.570 0.000 270.850 4.000 ;
    END
  END partial_sum16[0]
  PIN partial_sum16[10]
    DIRECTION OUTPUT ;
    USE SIGNAL ;
    ANTENNADIFFAREA 0.340600 ;
    PORT
      LAYER met2 ;
        RECT 284.370 0.000 284.650 4.000 ;
    END
  END partial_sum16[10]
  PIN partial_sum16[11]
    DIRECTION OUTPUT ;
    USE SIGNAL ;
    ANTENNADIFFAREA 0.340600 ;
    PORT
      LAYER met2 ;
        RECT 285.750 0.000 286.030 4.000 ;
    END
  END partial_sum16[11]
  PIN partial_sum16[12]
    DIRECTION OUTPUT ;
    USE SIGNAL ;
    ANTENNADIFFAREA 0.340600 ;
    PORT
      LAYER met2 ;
        RECT 287.130 0.000 287.410 4.000 ;
    END
  END partial_sum16[12]
  PIN partial_sum16[13]
    DIRECTION OUTPUT ;
    USE SIGNAL ;
    ANTENNADIFFAREA 0.340600 ;
    PORT
      LAYER met2 ;
        RECT 288.510 0.000 288.790 4.000 ;
    END
  END partial_sum16[13]
  PIN partial_sum16[14]
    DIRECTION OUTPUT ;
    USE SIGNAL ;
    ANTENNADIFFAREA 0.340600 ;
    PORT
      LAYER met2 ;
        RECT 289.890 0.000 290.170 4.000 ;
    END
  END partial_sum16[14]
  PIN partial_sum16[15]
    DIRECTION OUTPUT ;
    USE SIGNAL ;
    ANTENNADIFFAREA 0.340600 ;
    PORT
      LAYER met2 ;
        RECT 291.270 0.000 291.550 4.000 ;
    END
  END partial_sum16[15]
  PIN partial_sum16[1]
    DIRECTION OUTPUT ;
    USE SIGNAL ;
    ANTENNADIFFAREA 0.340600 ;
    PORT
      LAYER met2 ;
        RECT 271.950 0.000 272.230 4.000 ;
    END
  END partial_sum16[1]
  PIN partial_sum16[2]
    DIRECTION OUTPUT ;
    USE SIGNAL ;
    ANTENNADIFFAREA 0.340600 ;
    PORT
      LAYER met2 ;
        RECT 273.330 0.000 273.610 4.000 ;
    END
  END partial_sum16[2]
  PIN partial_sum16[3]
    DIRECTION OUTPUT ;
    USE SIGNAL ;
    ANTENNADIFFAREA 0.340600 ;
    PORT
      LAYER met2 ;
        RECT 274.710 0.000 274.990 4.000 ;
    END
  END partial_sum16[3]
  PIN partial_sum16[4]
    DIRECTION OUTPUT ;
    USE SIGNAL ;
    ANTENNADIFFAREA 0.340600 ;
    PORT
      LAYER met2 ;
        RECT 276.090 0.000 276.370 4.000 ;
    END
  END partial_sum16[4]
  PIN partial_sum16[5]
    DIRECTION OUTPUT ;
    USE SIGNAL ;
    ANTENNADIFFAREA 0.340600 ;
    PORT
      LAYER met2 ;
        RECT 277.470 0.000 277.750 4.000 ;
    END
  END partial_sum16[5]
  PIN partial_sum16[6]
    DIRECTION OUTPUT ;
    USE SIGNAL ;
    ANTENNADIFFAREA 0.340600 ;
    PORT
      LAYER met2 ;
        RECT 278.850 0.000 279.130 4.000 ;
    END
  END partial_sum16[6]
  PIN partial_sum16[7]
    DIRECTION OUTPUT ;
    USE SIGNAL ;
    ANTENNADIFFAREA 0.340600 ;
    PORT
      LAYER met2 ;
        RECT 280.230 0.000 280.510 4.000 ;
    END
  END partial_sum16[7]
  PIN partial_sum16[8]
    DIRECTION OUTPUT ;
    USE SIGNAL ;
    ANTENNADIFFAREA 0.340600 ;
    PORT
      LAYER met2 ;
        RECT 281.610 0.000 281.890 4.000 ;
    END
  END partial_sum16[8]
  PIN partial_sum16[9]
    DIRECTION OUTPUT ;
    USE SIGNAL ;
    ANTENNADIFFAREA 0.340600 ;
    PORT
      LAYER met2 ;
        RECT 282.990 0.000 283.270 4.000 ;
    END
  END partial_sum16[9]
  PIN rst
    DIRECTION INPUT ;
    USE SIGNAL ;
    ANTENNAGATEAREA 0.426000 ;
    PORT
      LAYER met3 ;
        RECT 296.000 198.600 300.000 199.200 ;
    END
  END rst
  PIN sum_out1[0]
    DIRECTION OUTPUT ;
    USE SIGNAL ;
    ANTENNADIFFAREA 0.340600 ;
    PORT
      LAYER met3 ;
        RECT 0.000 254.360 4.000 254.960 ;
    END
  END sum_out1[0]
  PIN sum_out1[10]
    DIRECTION OUTPUT ;
    USE SIGNAL ;
    ANTENNADIFFAREA 0.340600 ;
    PORT
      LAYER met3 ;
        RECT 0.000 267.960 4.000 268.560 ;
    END
  END sum_out1[10]
  PIN sum_out1[11]
    DIRECTION OUTPUT ;
    USE SIGNAL ;
    ANTENNADIFFAREA 0.340600 ;
    PORT
      LAYER met3 ;
        RECT 0.000 269.320 4.000 269.920 ;
    END
  END sum_out1[11]
  PIN sum_out1[1]
    DIRECTION OUTPUT ;
    USE SIGNAL ;
    ANTENNADIFFAREA 0.340600 ;
    PORT
      LAYER met3 ;
        RECT 0.000 255.720 4.000 256.320 ;
    END
  END sum_out1[1]
  PIN sum_out1[2]
    DIRECTION OUTPUT ;
    USE SIGNAL ;
    ANTENNADIFFAREA 0.340600 ;
    PORT
      LAYER met3 ;
        RECT 0.000 257.080 4.000 257.680 ;
    END
  END sum_out1[2]
  PIN sum_out1[3]
    DIRECTION OUTPUT ;
    USE SIGNAL ;
    ANTENNADIFFAREA 0.340600 ;
    PORT
      LAYER met3 ;
        RECT 0.000 258.440 4.000 259.040 ;
    END
  END sum_out1[3]
  PIN sum_out1[4]
    DIRECTION OUTPUT ;
    USE SIGNAL ;
    ANTENNADIFFAREA 0.340600 ;
    PORT
      LAYER met3 ;
        RECT 0.000 259.800 4.000 260.400 ;
    END
  END sum_out1[4]
  PIN sum_out1[5]
    DIRECTION OUTPUT ;
    USE SIGNAL ;
    ANTENNADIFFAREA 0.340600 ;
    PORT
      LAYER met3 ;
        RECT 0.000 261.160 4.000 261.760 ;
    END
  END sum_out1[5]
  PIN sum_out1[6]
    DIRECTION OUTPUT ;
    USE SIGNAL ;
    ANTENNADIFFAREA 0.340600 ;
    PORT
      LAYER met3 ;
        RECT 0.000 262.520 4.000 263.120 ;
    END
  END sum_out1[6]
  PIN sum_out1[7]
    DIRECTION OUTPUT ;
    USE SIGNAL ;
    ANTENNADIFFAREA 0.340600 ;
    PORT
      LAYER met3 ;
        RECT 0.000 263.880 4.000 264.480 ;
    END
  END sum_out1[7]
  PIN sum_out1[8]
    DIRECTION OUTPUT ;
    USE SIGNAL ;
    ANTENNADIFFAREA 0.340600 ;
    PORT
      LAYER met3 ;
        RECT 0.000 265.240 4.000 265.840 ;
    END
  END sum_out1[8]
  PIN sum_out1[9]
    DIRECTION OUTPUT ;
    USE SIGNAL ;
    ANTENNADIFFAREA 0.340600 ;
    PORT
      LAYER met3 ;
        RECT 0.000 266.600 4.000 267.200 ;
    END
  END sum_out1[9]
  PIN sum_out2[0]
    DIRECTION OUTPUT ;
    USE SIGNAL ;
    ANTENNADIFFAREA 0.340600 ;
    PORT
      LAYER met3 ;
        RECT 0.000 270.680 4.000 271.280 ;
    END
  END sum_out2[0]
  PIN sum_out2[10]
    DIRECTION OUTPUT ;
    USE SIGNAL ;
    ANTENNADIFFAREA 0.340600 ;
    PORT
      LAYER met3 ;
        RECT 0.000 284.280 4.000 284.880 ;
    END
  END sum_out2[10]
  PIN sum_out2[11]
    DIRECTION OUTPUT ;
    USE SIGNAL ;
    ANTENNADIFFAREA 0.340600 ;
    PORT
      LAYER met3 ;
        RECT 0.000 285.640 4.000 286.240 ;
    END
  END sum_out2[11]
  PIN sum_out2[1]
    DIRECTION OUTPUT ;
    USE SIGNAL ;
    ANTENNADIFFAREA 0.340600 ;
    PORT
      LAYER met3 ;
        RECT 0.000 272.040 4.000 272.640 ;
    END
  END sum_out2[1]
  PIN sum_out2[2]
    DIRECTION OUTPUT ;
    USE SIGNAL ;
    ANTENNADIFFAREA 0.340600 ;
    PORT
      LAYER met3 ;
        RECT 0.000 273.400 4.000 274.000 ;
    END
  END sum_out2[2]
  PIN sum_out2[3]
    DIRECTION OUTPUT ;
    USE SIGNAL ;
    ANTENNADIFFAREA 0.340600 ;
    PORT
      LAYER met3 ;
        RECT 0.000 274.760 4.000 275.360 ;
    END
  END sum_out2[3]
  PIN sum_out2[4]
    DIRECTION OUTPUT ;
    USE SIGNAL ;
    ANTENNADIFFAREA 0.340600 ;
    PORT
      LAYER met3 ;
        RECT 0.000 276.120 4.000 276.720 ;
    END
  END sum_out2[4]
  PIN sum_out2[5]
    DIRECTION OUTPUT ;
    USE SIGNAL ;
    ANTENNADIFFAREA 0.340600 ;
    PORT
      LAYER met3 ;
        RECT 0.000 277.480 4.000 278.080 ;
    END
  END sum_out2[5]
  PIN sum_out2[6]
    DIRECTION OUTPUT ;
    USE SIGNAL ;
    ANTENNADIFFAREA 0.340600 ;
    PORT
      LAYER met3 ;
        RECT 0.000 278.840 4.000 279.440 ;
    END
  END sum_out2[6]
  PIN sum_out2[7]
    DIRECTION OUTPUT ;
    USE SIGNAL ;
    ANTENNADIFFAREA 0.340600 ;
    PORT
      LAYER met3 ;
        RECT 0.000 280.200 4.000 280.800 ;
    END
  END sum_out2[7]
  PIN sum_out2[8]
    DIRECTION OUTPUT ;
    USE SIGNAL ;
    ANTENNADIFFAREA 0.340600 ;
    PORT
      LAYER met3 ;
        RECT 0.000 281.560 4.000 282.160 ;
    END
  END sum_out2[8]
  PIN sum_out2[9]
    DIRECTION OUTPUT ;
    USE SIGNAL ;
    ANTENNADIFFAREA 0.340600 ;
    PORT
      LAYER met3 ;
        RECT 0.000 282.920 4.000 283.520 ;
    END
  END sum_out2[9]
  PIN sum_out3[0]
    DIRECTION OUTPUT ;
    USE SIGNAL ;
    ANTENNADIFFAREA 0.340600 ;
    PORT
      LAYER met3 ;
        RECT 0.000 287.000 4.000 287.600 ;
    END
  END sum_out3[0]
  PIN sum_out3[10]
    DIRECTION OUTPUT ;
    USE SIGNAL ;
    ANTENNADIFFAREA 0.340600 ;
    PORT
      LAYER met3 ;
        RECT 0.000 300.600 4.000 301.200 ;
    END
  END sum_out3[10]
  PIN sum_out3[11]
    DIRECTION OUTPUT ;
    USE SIGNAL ;
    ANTENNADIFFAREA 0.340600 ;
    PORT
      LAYER met3 ;
        RECT 0.000 301.960 4.000 302.560 ;
    END
  END sum_out3[11]
  PIN sum_out3[1]
    DIRECTION OUTPUT ;
    USE SIGNAL ;
    ANTENNADIFFAREA 0.340600 ;
    PORT
      LAYER met3 ;
        RECT 0.000 288.360 4.000 288.960 ;
    END
  END sum_out3[1]
  PIN sum_out3[2]
    DIRECTION OUTPUT ;
    USE SIGNAL ;
    ANTENNADIFFAREA 0.340600 ;
    PORT
      LAYER met3 ;
        RECT 0.000 289.720 4.000 290.320 ;
    END
  END sum_out3[2]
  PIN sum_out3[3]
    DIRECTION OUTPUT ;
    USE SIGNAL ;
    ANTENNADIFFAREA 0.340600 ;
    PORT
      LAYER met3 ;
        RECT 0.000 291.080 4.000 291.680 ;
    END
  END sum_out3[3]
  PIN sum_out3[4]
    DIRECTION OUTPUT ;
    USE SIGNAL ;
    ANTENNADIFFAREA 0.340600 ;
    PORT
      LAYER met3 ;
        RECT 0.000 292.440 4.000 293.040 ;
    END
  END sum_out3[4]
  PIN sum_out3[5]
    DIRECTION OUTPUT ;
    USE SIGNAL ;
    ANTENNADIFFAREA 0.340600 ;
    PORT
      LAYER met3 ;
        RECT 0.000 293.800 4.000 294.400 ;
    END
  END sum_out3[5]
  PIN sum_out3[6]
    DIRECTION OUTPUT ;
    USE SIGNAL ;
    ANTENNADIFFAREA 0.340600 ;
    PORT
      LAYER met3 ;
        RECT 0.000 295.160 4.000 295.760 ;
    END
  END sum_out3[6]
  PIN sum_out3[7]
    DIRECTION OUTPUT ;
    USE SIGNAL ;
    ANTENNADIFFAREA 0.340600 ;
    PORT
      LAYER met3 ;
        RECT 0.000 296.520 4.000 297.120 ;
    END
  END sum_out3[7]
  PIN sum_out3[8]
    DIRECTION OUTPUT ;
    USE SIGNAL ;
    ANTENNADIFFAREA 0.340600 ;
    PORT
      LAYER met3 ;
        RECT 0.000 297.880 4.000 298.480 ;
    END
  END sum_out3[8]
  PIN sum_out3[9]
    DIRECTION OUTPUT ;
    USE SIGNAL ;
    ANTENNADIFFAREA 0.340600 ;
    PORT
      LAYER met3 ;
        RECT 0.000 299.240 4.000 299.840 ;
    END
  END sum_out3[9]
  PIN sum_out4[0]
    DIRECTION OUTPUT ;
    USE SIGNAL ;
    ANTENNADIFFAREA 0.340600 ;
    PORT
      LAYER met3 ;
        RECT 0.000 303.320 4.000 303.920 ;
    END
  END sum_out4[0]
  PIN sum_out4[10]
    DIRECTION OUTPUT ;
    USE SIGNAL ;
    ANTENNADIFFAREA 0.340600 ;
    PORT
      LAYER met3 ;
        RECT 0.000 316.920 4.000 317.520 ;
    END
  END sum_out4[10]
  PIN sum_out4[11]
    DIRECTION OUTPUT ;
    USE SIGNAL ;
    ANTENNADIFFAREA 0.340600 ;
    PORT
      LAYER met3 ;
        RECT 0.000 318.280 4.000 318.880 ;
    END
  END sum_out4[11]
  PIN sum_out4[1]
    DIRECTION OUTPUT ;
    USE SIGNAL ;
    ANTENNADIFFAREA 0.340600 ;
    PORT
      LAYER met3 ;
        RECT 0.000 304.680 4.000 305.280 ;
    END
  END sum_out4[1]
  PIN sum_out4[2]
    DIRECTION OUTPUT ;
    USE SIGNAL ;
    ANTENNADIFFAREA 0.340600 ;
    PORT
      LAYER met3 ;
        RECT 0.000 306.040 4.000 306.640 ;
    END
  END sum_out4[2]
  PIN sum_out4[3]
    DIRECTION OUTPUT ;
    USE SIGNAL ;
    ANTENNADIFFAREA 0.340600 ;
    PORT
      LAYER met3 ;
        RECT 0.000 307.400 4.000 308.000 ;
    END
  END sum_out4[3]
  PIN sum_out4[4]
    DIRECTION OUTPUT ;
    USE SIGNAL ;
    ANTENNADIFFAREA 0.340600 ;
    PORT
      LAYER met3 ;
        RECT 0.000 308.760 4.000 309.360 ;
    END
  END sum_out4[4]
  PIN sum_out4[5]
    DIRECTION OUTPUT ;
    USE SIGNAL ;
    ANTENNADIFFAREA 0.340600 ;
    PORT
      LAYER met3 ;
        RECT 0.000 310.120 4.000 310.720 ;
    END
  END sum_out4[5]
  PIN sum_out4[6]
    DIRECTION OUTPUT ;
    USE SIGNAL ;
    ANTENNADIFFAREA 0.340600 ;
    PORT
      LAYER met3 ;
        RECT 0.000 311.480 4.000 312.080 ;
    END
  END sum_out4[6]
  PIN sum_out4[7]
    DIRECTION OUTPUT ;
    USE SIGNAL ;
    ANTENNADIFFAREA 0.340600 ;
    PORT
      LAYER met3 ;
        RECT 0.000 312.840 4.000 313.440 ;
    END
  END sum_out4[7]
  PIN sum_out4[8]
    DIRECTION OUTPUT ;
    USE SIGNAL ;
    ANTENNADIFFAREA 0.340600 ;
    PORT
      LAYER met3 ;
        RECT 0.000 314.200 4.000 314.800 ;
    END
  END sum_out4[8]
  PIN sum_out4[9]
    DIRECTION OUTPUT ;
    USE SIGNAL ;
    ANTENNADIFFAREA 0.340600 ;
    PORT
      LAYER met3 ;
        RECT 0.000 315.560 4.000 316.160 ;
    END
  END sum_out4[9]
  PIN sum_out5[0]
    DIRECTION OUTPUT ;
    USE SIGNAL ;
    ANTENNADIFFAREA 0.340600 ;
    PORT
      LAYER met3 ;
        RECT 0.000 319.640 4.000 320.240 ;
    END
  END sum_out5[0]
  PIN sum_out5[10]
    DIRECTION OUTPUT ;
    USE SIGNAL ;
    ANTENNADIFFAREA 0.340600 ;
    PORT
      LAYER met3 ;
        RECT 0.000 333.240 4.000 333.840 ;
    END
  END sum_out5[10]
  PIN sum_out5[11]
    DIRECTION OUTPUT ;
    USE SIGNAL ;
    ANTENNADIFFAREA 0.340600 ;
    PORT
      LAYER met3 ;
        RECT 0.000 334.600 4.000 335.200 ;
    END
  END sum_out5[11]
  PIN sum_out5[1]
    DIRECTION OUTPUT ;
    USE SIGNAL ;
    ANTENNADIFFAREA 0.340600 ;
    PORT
      LAYER met3 ;
        RECT 0.000 321.000 4.000 321.600 ;
    END
  END sum_out5[1]
  PIN sum_out5[2]
    DIRECTION OUTPUT ;
    USE SIGNAL ;
    ANTENNADIFFAREA 0.340600 ;
    PORT
      LAYER met3 ;
        RECT 0.000 322.360 4.000 322.960 ;
    END
  END sum_out5[2]
  PIN sum_out5[3]
    DIRECTION OUTPUT ;
    USE SIGNAL ;
    ANTENNADIFFAREA 0.340600 ;
    PORT
      LAYER met3 ;
        RECT 0.000 323.720 4.000 324.320 ;
    END
  END sum_out5[3]
  PIN sum_out5[4]
    DIRECTION OUTPUT ;
    USE SIGNAL ;
    ANTENNADIFFAREA 0.340600 ;
    PORT
      LAYER met3 ;
        RECT 0.000 325.080 4.000 325.680 ;
    END
  END sum_out5[4]
  PIN sum_out5[5]
    DIRECTION OUTPUT ;
    USE SIGNAL ;
    ANTENNADIFFAREA 0.340600 ;
    PORT
      LAYER met3 ;
        RECT 0.000 326.440 4.000 327.040 ;
    END
  END sum_out5[5]
  PIN sum_out5[6]
    DIRECTION OUTPUT ;
    USE SIGNAL ;
    ANTENNADIFFAREA 0.340600 ;
    PORT
      LAYER met3 ;
        RECT 0.000 327.800 4.000 328.400 ;
    END
  END sum_out5[6]
  PIN sum_out5[7]
    DIRECTION OUTPUT ;
    USE SIGNAL ;
    ANTENNADIFFAREA 0.340600 ;
    PORT
      LAYER met3 ;
        RECT 0.000 329.160 4.000 329.760 ;
    END
  END sum_out5[7]
  PIN sum_out5[8]
    DIRECTION OUTPUT ;
    USE SIGNAL ;
    ANTENNADIFFAREA 0.340600 ;
    PORT
      LAYER met3 ;
        RECT 0.000 330.520 4.000 331.120 ;
    END
  END sum_out5[8]
  PIN sum_out5[9]
    DIRECTION OUTPUT ;
    USE SIGNAL ;
    ANTENNADIFFAREA 0.340600 ;
    PORT
      LAYER met3 ;
        RECT 0.000 331.880 4.000 332.480 ;
    END
  END sum_out5[9]
  PIN sum_out6[0]
    DIRECTION OUTPUT ;
    USE SIGNAL ;
    ANTENNADIFFAREA 0.340600 ;
    PORT
      LAYER met3 ;
        RECT 0.000 335.960 4.000 336.560 ;
    END
  END sum_out6[0]
  PIN sum_out6[10]
    DIRECTION OUTPUT ;
    USE SIGNAL ;
    ANTENNADIFFAREA 0.340600 ;
    PORT
      LAYER met3 ;
        RECT 0.000 349.560 4.000 350.160 ;
    END
  END sum_out6[10]
  PIN sum_out6[11]
    DIRECTION OUTPUT ;
    USE SIGNAL ;
    ANTENNADIFFAREA 0.340600 ;
    PORT
      LAYER met3 ;
        RECT 0.000 350.920 4.000 351.520 ;
    END
  END sum_out6[11]
  PIN sum_out6[1]
    DIRECTION OUTPUT ;
    USE SIGNAL ;
    ANTENNADIFFAREA 0.340600 ;
    PORT
      LAYER met3 ;
        RECT 0.000 337.320 4.000 337.920 ;
    END
  END sum_out6[1]
  PIN sum_out6[2]
    DIRECTION OUTPUT ;
    USE SIGNAL ;
    ANTENNADIFFAREA 0.340600 ;
    PORT
      LAYER met3 ;
        RECT 0.000 338.680 4.000 339.280 ;
    END
  END sum_out6[2]
  PIN sum_out6[3]
    DIRECTION OUTPUT ;
    USE SIGNAL ;
    ANTENNADIFFAREA 0.340600 ;
    PORT
      LAYER met3 ;
        RECT 0.000 340.040 4.000 340.640 ;
    END
  END sum_out6[3]
  PIN sum_out6[4]
    DIRECTION OUTPUT ;
    USE SIGNAL ;
    ANTENNADIFFAREA 0.340600 ;
    PORT
      LAYER met3 ;
        RECT 0.000 341.400 4.000 342.000 ;
    END
  END sum_out6[4]
  PIN sum_out6[5]
    DIRECTION OUTPUT ;
    USE SIGNAL ;
    ANTENNADIFFAREA 0.340600 ;
    PORT
      LAYER met3 ;
        RECT 0.000 342.760 4.000 343.360 ;
    END
  END sum_out6[5]
  PIN sum_out6[6]
    DIRECTION OUTPUT ;
    USE SIGNAL ;
    ANTENNADIFFAREA 0.340600 ;
    PORT
      LAYER met3 ;
        RECT 0.000 344.120 4.000 344.720 ;
    END
  END sum_out6[6]
  PIN sum_out6[7]
    DIRECTION OUTPUT ;
    USE SIGNAL ;
    ANTENNADIFFAREA 0.340600 ;
    PORT
      LAYER met3 ;
        RECT 0.000 345.480 4.000 346.080 ;
    END
  END sum_out6[7]
  PIN sum_out6[8]
    DIRECTION OUTPUT ;
    USE SIGNAL ;
    ANTENNADIFFAREA 0.340600 ;
    PORT
      LAYER met3 ;
        RECT 0.000 346.840 4.000 347.440 ;
    END
  END sum_out6[8]
  PIN sum_out6[9]
    DIRECTION OUTPUT ;
    USE SIGNAL ;
    ANTENNADIFFAREA 0.340600 ;
    PORT
      LAYER met3 ;
        RECT 0.000 348.200 4.000 348.800 ;
    END
  END sum_out6[9]
  PIN sum_out7[0]
    DIRECTION OUTPUT ;
    USE SIGNAL ;
    ANTENNADIFFAREA 0.340600 ;
    PORT
      LAYER met3 ;
        RECT 0.000 352.280 4.000 352.880 ;
    END
  END sum_out7[0]
  PIN sum_out7[10]
    DIRECTION OUTPUT ;
    USE SIGNAL ;
    ANTENNADIFFAREA 0.340600 ;
    PORT
      LAYER met3 ;
        RECT 0.000 365.880 4.000 366.480 ;
    END
  END sum_out7[10]
  PIN sum_out7[11]
    DIRECTION OUTPUT ;
    USE SIGNAL ;
    ANTENNADIFFAREA 0.340600 ;
    PORT
      LAYER met3 ;
        RECT 0.000 367.240 4.000 367.840 ;
    END
  END sum_out7[11]
  PIN sum_out7[1]
    DIRECTION OUTPUT ;
    USE SIGNAL ;
    ANTENNADIFFAREA 0.340600 ;
    PORT
      LAYER met3 ;
        RECT 0.000 353.640 4.000 354.240 ;
    END
  END sum_out7[1]
  PIN sum_out7[2]
    DIRECTION OUTPUT ;
    USE SIGNAL ;
    ANTENNADIFFAREA 0.340600 ;
    PORT
      LAYER met3 ;
        RECT 0.000 355.000 4.000 355.600 ;
    END
  END sum_out7[2]
  PIN sum_out7[3]
    DIRECTION OUTPUT ;
    USE SIGNAL ;
    ANTENNADIFFAREA 0.340600 ;
    PORT
      LAYER met3 ;
        RECT 0.000 356.360 4.000 356.960 ;
    END
  END sum_out7[3]
  PIN sum_out7[4]
    DIRECTION OUTPUT ;
    USE SIGNAL ;
    ANTENNADIFFAREA 0.340600 ;
    PORT
      LAYER met3 ;
        RECT 0.000 357.720 4.000 358.320 ;
    END
  END sum_out7[4]
  PIN sum_out7[5]
    DIRECTION OUTPUT ;
    USE SIGNAL ;
    ANTENNADIFFAREA 0.340600 ;
    PORT
      LAYER met3 ;
        RECT 0.000 359.080 4.000 359.680 ;
    END
  END sum_out7[5]
  PIN sum_out7[6]
    DIRECTION OUTPUT ;
    USE SIGNAL ;
    ANTENNADIFFAREA 0.340600 ;
    PORT
      LAYER met3 ;
        RECT 0.000 360.440 4.000 361.040 ;
    END
  END sum_out7[6]
  PIN sum_out7[7]
    DIRECTION OUTPUT ;
    USE SIGNAL ;
    ANTENNADIFFAREA 0.340600 ;
    PORT
      LAYER met3 ;
        RECT 0.000 361.800 4.000 362.400 ;
    END
  END sum_out7[7]
  PIN sum_out7[8]
    DIRECTION OUTPUT ;
    USE SIGNAL ;
    ANTENNADIFFAREA 0.340600 ;
    PORT
      LAYER met3 ;
        RECT 0.000 363.160 4.000 363.760 ;
    END
  END sum_out7[8]
  PIN sum_out7[9]
    DIRECTION OUTPUT ;
    USE SIGNAL ;
    ANTENNADIFFAREA 0.340600 ;
    PORT
      LAYER met3 ;
        RECT 0.000 364.520 4.000 365.120 ;
    END
  END sum_out7[9]
  PIN sum_out8[0]
    DIRECTION OUTPUT ;
    USE SIGNAL ;
    ANTENNADIFFAREA 0.340600 ;
    PORT
      LAYER met3 ;
        RECT 0.000 368.600 4.000 369.200 ;
    END
  END sum_out8[0]
  PIN sum_out8[10]
    DIRECTION OUTPUT ;
    USE SIGNAL ;
    ANTENNADIFFAREA 0.340600 ;
    PORT
      LAYER met3 ;
        RECT 0.000 382.200 4.000 382.800 ;
    END
  END sum_out8[10]
  PIN sum_out8[11]
    DIRECTION OUTPUT ;
    USE SIGNAL ;
    ANTENNADIFFAREA 0.340600 ;
    PORT
      LAYER met3 ;
        RECT 0.000 383.560 4.000 384.160 ;
    END
  END sum_out8[11]
  PIN sum_out8[1]
    DIRECTION OUTPUT ;
    USE SIGNAL ;
    ANTENNADIFFAREA 0.340600 ;
    PORT
      LAYER met3 ;
        RECT 0.000 369.960 4.000 370.560 ;
    END
  END sum_out8[1]
  PIN sum_out8[2]
    DIRECTION OUTPUT ;
    USE SIGNAL ;
    ANTENNADIFFAREA 0.340600 ;
    PORT
      LAYER met3 ;
        RECT 0.000 371.320 4.000 371.920 ;
    END
  END sum_out8[2]
  PIN sum_out8[3]
    DIRECTION OUTPUT ;
    USE SIGNAL ;
    ANTENNADIFFAREA 0.340600 ;
    PORT
      LAYER met3 ;
        RECT 0.000 372.680 4.000 373.280 ;
    END
  END sum_out8[3]
  PIN sum_out8[4]
    DIRECTION OUTPUT ;
    USE SIGNAL ;
    ANTENNADIFFAREA 0.340600 ;
    PORT
      LAYER met3 ;
        RECT 0.000 374.040 4.000 374.640 ;
    END
  END sum_out8[4]
  PIN sum_out8[5]
    DIRECTION OUTPUT ;
    USE SIGNAL ;
    ANTENNADIFFAREA 0.340600 ;
    PORT
      LAYER met3 ;
        RECT 0.000 375.400 4.000 376.000 ;
    END
  END sum_out8[5]
  PIN sum_out8[6]
    DIRECTION OUTPUT ;
    USE SIGNAL ;
    ANTENNADIFFAREA 0.340600 ;
    PORT
      LAYER met3 ;
        RECT 0.000 376.760 4.000 377.360 ;
    END
  END sum_out8[6]
  PIN sum_out8[7]
    DIRECTION OUTPUT ;
    USE SIGNAL ;
    ANTENNADIFFAREA 0.340600 ;
    PORT
      LAYER met3 ;
        RECT 0.000 378.120 4.000 378.720 ;
    END
  END sum_out8[7]
  PIN sum_out8[8]
    DIRECTION OUTPUT ;
    USE SIGNAL ;
    ANTENNADIFFAREA 0.340600 ;
    PORT
      LAYER met3 ;
        RECT 0.000 379.480 4.000 380.080 ;
    END
  END sum_out8[8]
  PIN sum_out8[9]
    DIRECTION OUTPUT ;
    USE SIGNAL ;
    ANTENNADIFFAREA 0.340600 ;
    PORT
      LAYER met3 ;
        RECT 0.000 380.840 4.000 381.440 ;
    END
  END sum_out8[9]
  OBS
      LAYER nwell ;
        RECT 5.330 10.795 294.590 389.150 ;
      LAYER li1 ;
        RECT 5.520 10.795 294.400 389.045 ;
      LAYER met1 ;
        RECT 0.990 5.140 294.400 391.300 ;
      LAYER met2 ;
        RECT 1.020 395.720 7.170 396.170 ;
        RECT 8.010 395.720 9.930 396.170 ;
        RECT 10.770 395.720 12.690 396.170 ;
        RECT 13.530 395.720 15.450 396.170 ;
        RECT 16.290 395.720 18.210 396.170 ;
        RECT 19.050 395.720 20.970 396.170 ;
        RECT 21.810 395.720 23.730 396.170 ;
        RECT 24.570 395.720 26.490 396.170 ;
        RECT 27.330 395.720 29.250 396.170 ;
        RECT 30.090 395.720 32.010 396.170 ;
        RECT 32.850 395.720 34.770 396.170 ;
        RECT 35.610 395.720 37.530 396.170 ;
        RECT 38.370 395.720 40.290 396.170 ;
        RECT 41.130 395.720 43.050 396.170 ;
        RECT 43.890 395.720 45.810 396.170 ;
        RECT 46.650 395.720 48.570 396.170 ;
        RECT 49.410 395.720 51.330 396.170 ;
        RECT 52.170 395.720 54.090 396.170 ;
        RECT 54.930 395.720 56.850 396.170 ;
        RECT 57.690 395.720 59.610 396.170 ;
        RECT 60.450 395.720 62.370 396.170 ;
        RECT 63.210 395.720 65.130 396.170 ;
        RECT 65.970 395.720 67.890 396.170 ;
        RECT 68.730 395.720 70.650 396.170 ;
        RECT 71.490 395.720 73.410 396.170 ;
        RECT 74.250 395.720 76.170 396.170 ;
        RECT 77.010 395.720 78.930 396.170 ;
        RECT 79.770 395.720 81.690 396.170 ;
        RECT 82.530 395.720 84.450 396.170 ;
        RECT 85.290 395.720 87.210 396.170 ;
        RECT 88.050 395.720 89.970 396.170 ;
        RECT 90.810 395.720 92.730 396.170 ;
        RECT 93.570 395.720 95.490 396.170 ;
        RECT 96.330 395.720 98.250 396.170 ;
        RECT 99.090 395.720 101.010 396.170 ;
        RECT 101.850 395.720 103.770 396.170 ;
        RECT 104.610 395.720 106.530 396.170 ;
        RECT 107.370 395.720 109.290 396.170 ;
        RECT 110.130 395.720 112.050 396.170 ;
        RECT 112.890 395.720 114.810 396.170 ;
        RECT 115.650 395.720 117.570 396.170 ;
        RECT 118.410 395.720 120.330 396.170 ;
        RECT 121.170 395.720 123.090 396.170 ;
        RECT 123.930 395.720 125.850 396.170 ;
        RECT 126.690 395.720 128.610 396.170 ;
        RECT 129.450 395.720 131.370 396.170 ;
        RECT 132.210 395.720 134.130 396.170 ;
        RECT 134.970 395.720 136.890 396.170 ;
        RECT 137.730 395.720 139.650 396.170 ;
        RECT 140.490 395.720 142.410 396.170 ;
        RECT 143.250 395.720 145.170 396.170 ;
        RECT 146.010 395.720 147.930 396.170 ;
        RECT 148.770 395.720 150.690 396.170 ;
        RECT 151.530 395.720 153.450 396.170 ;
        RECT 154.290 395.720 156.210 396.170 ;
        RECT 157.050 395.720 158.970 396.170 ;
        RECT 159.810 395.720 161.730 396.170 ;
        RECT 162.570 395.720 164.490 396.170 ;
        RECT 165.330 395.720 167.250 396.170 ;
        RECT 168.090 395.720 170.010 396.170 ;
        RECT 170.850 395.720 172.770 396.170 ;
        RECT 173.610 395.720 175.530 396.170 ;
        RECT 176.370 395.720 178.290 396.170 ;
        RECT 179.130 395.720 181.050 396.170 ;
        RECT 181.890 395.720 183.810 396.170 ;
        RECT 184.650 395.720 186.570 396.170 ;
        RECT 187.410 395.720 189.330 396.170 ;
        RECT 190.170 395.720 192.090 396.170 ;
        RECT 192.930 395.720 194.850 396.170 ;
        RECT 195.690 395.720 197.610 396.170 ;
        RECT 198.450 395.720 200.370 396.170 ;
        RECT 201.210 395.720 203.130 396.170 ;
        RECT 203.970 395.720 205.890 396.170 ;
        RECT 206.730 395.720 208.650 396.170 ;
        RECT 209.490 395.720 211.410 396.170 ;
        RECT 212.250 395.720 214.170 396.170 ;
        RECT 215.010 395.720 216.930 396.170 ;
        RECT 217.770 395.720 219.690 396.170 ;
        RECT 220.530 395.720 222.450 396.170 ;
        RECT 223.290 395.720 225.210 396.170 ;
        RECT 226.050 395.720 227.970 396.170 ;
        RECT 228.810 395.720 230.730 396.170 ;
        RECT 231.570 395.720 233.490 396.170 ;
        RECT 234.330 395.720 236.250 396.170 ;
        RECT 237.090 395.720 239.010 396.170 ;
        RECT 239.850 395.720 241.770 396.170 ;
        RECT 242.610 395.720 244.530 396.170 ;
        RECT 245.370 395.720 247.290 396.170 ;
        RECT 248.130 395.720 250.050 396.170 ;
        RECT 250.890 395.720 252.810 396.170 ;
        RECT 253.650 395.720 255.570 396.170 ;
        RECT 256.410 395.720 258.330 396.170 ;
        RECT 259.170 395.720 261.090 396.170 ;
        RECT 261.930 395.720 263.850 396.170 ;
        RECT 264.690 395.720 266.610 396.170 ;
        RECT 267.450 395.720 269.370 396.170 ;
        RECT 270.210 395.720 272.130 396.170 ;
        RECT 272.970 395.720 274.890 396.170 ;
        RECT 275.730 395.720 277.650 396.170 ;
        RECT 278.490 395.720 280.410 396.170 ;
        RECT 281.250 395.720 283.170 396.170 ;
        RECT 284.010 395.720 285.930 396.170 ;
        RECT 286.770 395.720 288.690 396.170 ;
        RECT 289.530 395.720 291.450 396.170 ;
        RECT 292.290 395.720 293.390 396.170 ;
        RECT 1.020 4.280 293.390 395.720 ;
        RECT 1.020 4.000 8.090 4.280 ;
        RECT 8.930 4.000 9.470 4.280 ;
        RECT 10.310 4.000 10.850 4.280 ;
        RECT 11.690 4.000 12.230 4.280 ;
        RECT 13.070 4.000 13.610 4.280 ;
        RECT 14.450 4.000 14.990 4.280 ;
        RECT 15.830 4.000 16.370 4.280 ;
        RECT 17.210 4.000 17.750 4.280 ;
        RECT 18.590 4.000 19.130 4.280 ;
        RECT 19.970 4.000 20.510 4.280 ;
        RECT 21.350 4.000 21.890 4.280 ;
        RECT 22.730 4.000 23.270 4.280 ;
        RECT 24.110 4.000 24.650 4.280 ;
        RECT 25.490 4.000 26.030 4.280 ;
        RECT 26.870 4.000 27.410 4.280 ;
        RECT 28.250 4.000 28.790 4.280 ;
        RECT 29.630 4.000 30.170 4.280 ;
        RECT 31.010 4.000 31.550 4.280 ;
        RECT 32.390 4.000 32.930 4.280 ;
        RECT 33.770 4.000 34.310 4.280 ;
        RECT 35.150 4.000 35.690 4.280 ;
        RECT 36.530 4.000 37.070 4.280 ;
        RECT 37.910 4.000 38.450 4.280 ;
        RECT 39.290 4.000 39.830 4.280 ;
        RECT 40.670 4.000 41.210 4.280 ;
        RECT 42.050 4.000 42.590 4.280 ;
        RECT 43.430 4.000 43.970 4.280 ;
        RECT 44.810 4.000 45.350 4.280 ;
        RECT 46.190 4.000 46.730 4.280 ;
        RECT 47.570 4.000 48.110 4.280 ;
        RECT 48.950 4.000 49.490 4.280 ;
        RECT 50.330 4.000 50.870 4.280 ;
        RECT 51.710 4.000 52.250 4.280 ;
        RECT 53.090 4.000 53.630 4.280 ;
        RECT 54.470 4.000 55.010 4.280 ;
        RECT 55.850 4.000 56.390 4.280 ;
        RECT 57.230 4.000 57.770 4.280 ;
        RECT 58.610 4.000 59.150 4.280 ;
        RECT 59.990 4.000 60.530 4.280 ;
        RECT 61.370 4.000 61.910 4.280 ;
        RECT 62.750 4.000 63.290 4.280 ;
        RECT 64.130 4.000 64.670 4.280 ;
        RECT 65.510 4.000 66.050 4.280 ;
        RECT 66.890 4.000 67.430 4.280 ;
        RECT 68.270 4.000 68.810 4.280 ;
        RECT 69.650 4.000 70.190 4.280 ;
        RECT 71.030 4.000 71.570 4.280 ;
        RECT 72.410 4.000 72.950 4.280 ;
        RECT 73.790 4.000 74.330 4.280 ;
        RECT 75.170 4.000 75.710 4.280 ;
        RECT 76.550 4.000 77.090 4.280 ;
        RECT 77.930 4.000 78.470 4.280 ;
        RECT 79.310 4.000 79.850 4.280 ;
        RECT 80.690 4.000 81.230 4.280 ;
        RECT 82.070 4.000 82.610 4.280 ;
        RECT 83.450 4.000 83.990 4.280 ;
        RECT 84.830 4.000 85.370 4.280 ;
        RECT 86.210 4.000 86.750 4.280 ;
        RECT 87.590 4.000 88.130 4.280 ;
        RECT 88.970 4.000 89.510 4.280 ;
        RECT 90.350 4.000 90.890 4.280 ;
        RECT 91.730 4.000 92.270 4.280 ;
        RECT 93.110 4.000 93.650 4.280 ;
        RECT 94.490 4.000 95.030 4.280 ;
        RECT 95.870 4.000 96.410 4.280 ;
        RECT 97.250 4.000 97.790 4.280 ;
        RECT 98.630 4.000 99.170 4.280 ;
        RECT 100.010 4.000 100.550 4.280 ;
        RECT 101.390 4.000 101.930 4.280 ;
        RECT 102.770 4.000 103.310 4.280 ;
        RECT 104.150 4.000 104.690 4.280 ;
        RECT 105.530 4.000 106.070 4.280 ;
        RECT 106.910 4.000 107.450 4.280 ;
        RECT 108.290 4.000 108.830 4.280 ;
        RECT 109.670 4.000 110.210 4.280 ;
        RECT 111.050 4.000 111.590 4.280 ;
        RECT 112.430 4.000 112.970 4.280 ;
        RECT 113.810 4.000 114.350 4.280 ;
        RECT 115.190 4.000 115.730 4.280 ;
        RECT 116.570 4.000 117.110 4.280 ;
        RECT 117.950 4.000 118.490 4.280 ;
        RECT 119.330 4.000 119.870 4.280 ;
        RECT 120.710 4.000 121.250 4.280 ;
        RECT 122.090 4.000 122.630 4.280 ;
        RECT 123.470 4.000 124.010 4.280 ;
        RECT 124.850 4.000 125.390 4.280 ;
        RECT 126.230 4.000 126.770 4.280 ;
        RECT 127.610 4.000 128.150 4.280 ;
        RECT 128.990 4.000 129.530 4.280 ;
        RECT 130.370 4.000 130.910 4.280 ;
        RECT 131.750 4.000 132.290 4.280 ;
        RECT 133.130 4.000 133.670 4.280 ;
        RECT 134.510 4.000 135.050 4.280 ;
        RECT 135.890 4.000 136.430 4.280 ;
        RECT 137.270 4.000 137.810 4.280 ;
        RECT 138.650 4.000 139.190 4.280 ;
        RECT 140.030 4.000 140.570 4.280 ;
        RECT 141.410 4.000 141.950 4.280 ;
        RECT 142.790 4.000 143.330 4.280 ;
        RECT 144.170 4.000 144.710 4.280 ;
        RECT 145.550 4.000 146.090 4.280 ;
        RECT 146.930 4.000 147.470 4.280 ;
        RECT 148.310 4.000 148.850 4.280 ;
        RECT 149.690 4.000 150.230 4.280 ;
        RECT 151.070 4.000 151.610 4.280 ;
        RECT 152.450 4.000 152.990 4.280 ;
        RECT 153.830 4.000 154.370 4.280 ;
        RECT 155.210 4.000 155.750 4.280 ;
        RECT 156.590 4.000 157.130 4.280 ;
        RECT 157.970 4.000 158.510 4.280 ;
        RECT 159.350 4.000 159.890 4.280 ;
        RECT 160.730 4.000 161.270 4.280 ;
        RECT 162.110 4.000 162.650 4.280 ;
        RECT 163.490 4.000 164.030 4.280 ;
        RECT 164.870 4.000 165.410 4.280 ;
        RECT 166.250 4.000 166.790 4.280 ;
        RECT 167.630 4.000 168.170 4.280 ;
        RECT 169.010 4.000 169.550 4.280 ;
        RECT 170.390 4.000 170.930 4.280 ;
        RECT 171.770 4.000 172.310 4.280 ;
        RECT 173.150 4.000 173.690 4.280 ;
        RECT 174.530 4.000 175.070 4.280 ;
        RECT 175.910 4.000 176.450 4.280 ;
        RECT 177.290 4.000 177.830 4.280 ;
        RECT 178.670 4.000 179.210 4.280 ;
        RECT 180.050 4.000 180.590 4.280 ;
        RECT 181.430 4.000 181.970 4.280 ;
        RECT 182.810 4.000 183.350 4.280 ;
        RECT 184.190 4.000 184.730 4.280 ;
        RECT 185.570 4.000 186.110 4.280 ;
        RECT 186.950 4.000 187.490 4.280 ;
        RECT 188.330 4.000 188.870 4.280 ;
        RECT 189.710 4.000 190.250 4.280 ;
        RECT 191.090 4.000 191.630 4.280 ;
        RECT 192.470 4.000 193.010 4.280 ;
        RECT 193.850 4.000 194.390 4.280 ;
        RECT 195.230 4.000 195.770 4.280 ;
        RECT 196.610 4.000 197.150 4.280 ;
        RECT 197.990 4.000 198.530 4.280 ;
        RECT 199.370 4.000 199.910 4.280 ;
        RECT 200.750 4.000 201.290 4.280 ;
        RECT 202.130 4.000 202.670 4.280 ;
        RECT 203.510 4.000 204.050 4.280 ;
        RECT 204.890 4.000 205.430 4.280 ;
        RECT 206.270 4.000 206.810 4.280 ;
        RECT 207.650 4.000 208.190 4.280 ;
        RECT 209.030 4.000 209.570 4.280 ;
        RECT 210.410 4.000 210.950 4.280 ;
        RECT 211.790 4.000 212.330 4.280 ;
        RECT 213.170 4.000 213.710 4.280 ;
        RECT 214.550 4.000 215.090 4.280 ;
        RECT 215.930 4.000 216.470 4.280 ;
        RECT 217.310 4.000 217.850 4.280 ;
        RECT 218.690 4.000 219.230 4.280 ;
        RECT 220.070 4.000 220.610 4.280 ;
        RECT 221.450 4.000 221.990 4.280 ;
        RECT 222.830 4.000 223.370 4.280 ;
        RECT 224.210 4.000 224.750 4.280 ;
        RECT 225.590 4.000 226.130 4.280 ;
        RECT 226.970 4.000 227.510 4.280 ;
        RECT 228.350 4.000 228.890 4.280 ;
        RECT 229.730 4.000 230.270 4.280 ;
        RECT 231.110 4.000 231.650 4.280 ;
        RECT 232.490 4.000 233.030 4.280 ;
        RECT 233.870 4.000 234.410 4.280 ;
        RECT 235.250 4.000 235.790 4.280 ;
        RECT 236.630 4.000 237.170 4.280 ;
        RECT 238.010 4.000 238.550 4.280 ;
        RECT 239.390 4.000 239.930 4.280 ;
        RECT 240.770 4.000 241.310 4.280 ;
        RECT 242.150 4.000 242.690 4.280 ;
        RECT 243.530 4.000 244.070 4.280 ;
        RECT 244.910 4.000 245.450 4.280 ;
        RECT 246.290 4.000 246.830 4.280 ;
        RECT 247.670 4.000 248.210 4.280 ;
        RECT 249.050 4.000 249.590 4.280 ;
        RECT 250.430 4.000 250.970 4.280 ;
        RECT 251.810 4.000 252.350 4.280 ;
        RECT 253.190 4.000 253.730 4.280 ;
        RECT 254.570 4.000 255.110 4.280 ;
        RECT 255.950 4.000 256.490 4.280 ;
        RECT 257.330 4.000 257.870 4.280 ;
        RECT 258.710 4.000 259.250 4.280 ;
        RECT 260.090 4.000 260.630 4.280 ;
        RECT 261.470 4.000 262.010 4.280 ;
        RECT 262.850 4.000 263.390 4.280 ;
        RECT 264.230 4.000 264.770 4.280 ;
        RECT 265.610 4.000 266.150 4.280 ;
        RECT 266.990 4.000 267.530 4.280 ;
        RECT 268.370 4.000 268.910 4.280 ;
        RECT 269.750 4.000 270.290 4.280 ;
        RECT 271.130 4.000 271.670 4.280 ;
        RECT 272.510 4.000 273.050 4.280 ;
        RECT 273.890 4.000 274.430 4.280 ;
        RECT 275.270 4.000 275.810 4.280 ;
        RECT 276.650 4.000 277.190 4.280 ;
        RECT 278.030 4.000 278.570 4.280 ;
        RECT 279.410 4.000 279.950 4.280 ;
        RECT 280.790 4.000 281.330 4.280 ;
        RECT 282.170 4.000 282.710 4.280 ;
        RECT 283.550 4.000 284.090 4.280 ;
        RECT 284.930 4.000 285.470 4.280 ;
        RECT 286.310 4.000 286.850 4.280 ;
        RECT 287.690 4.000 288.230 4.280 ;
        RECT 289.070 4.000 289.610 4.280 ;
        RECT 290.450 4.000 290.990 4.280 ;
        RECT 291.830 4.000 293.390 4.280 ;
      LAYER met3 ;
        RECT 3.990 384.560 296.000 389.125 ;
        RECT 4.400 332.880 296.000 384.560 ;
        RECT 4.400 331.480 295.600 332.880 ;
        RECT 4.400 199.600 296.000 331.480 ;
        RECT 4.400 198.200 295.600 199.600 ;
        RECT 4.400 66.320 296.000 198.200 ;
        RECT 4.400 64.920 295.600 66.320 ;
        RECT 4.400 14.600 296.000 64.920 ;
        RECT 3.990 4.935 296.000 14.600 ;
      LAYER met4 ;
        RECT 2.630 10.240 14.320 387.425 ;
        RECT 16.720 10.240 17.620 387.425 ;
        RECT 20.020 10.240 64.320 387.425 ;
        RECT 66.720 10.240 67.620 387.425 ;
        RECT 70.020 10.240 114.320 387.425 ;
        RECT 116.720 10.240 117.620 387.425 ;
        RECT 120.020 10.240 164.320 387.425 ;
        RECT 166.720 10.240 167.620 387.425 ;
        RECT 170.020 10.240 214.320 387.425 ;
        RECT 216.720 10.240 217.620 387.425 ;
        RECT 220.020 10.240 264.320 387.425 ;
        RECT 266.720 10.240 267.620 387.425 ;
        RECT 270.020 10.240 279.385 387.425 ;
        RECT 2.630 7.655 279.385 10.240 ;
      LAYER met5 ;
        RECT 2.420 326.580 228.500 339.100 ;
        RECT 2.420 318.480 3.680 326.580 ;
        RECT 2.420 276.580 228.500 318.480 ;
        RECT 2.420 268.480 3.680 276.580 ;
        RECT 2.420 226.580 228.500 268.480 ;
        RECT 2.420 218.480 3.680 226.580 ;
        RECT 2.420 176.580 228.500 218.480 ;
        RECT 2.420 168.480 3.680 176.580 ;
        RECT 2.420 126.580 228.500 168.480 ;
        RECT 2.420 118.480 3.680 126.580 ;
        RECT 2.420 76.580 228.500 118.480 ;
        RECT 2.420 68.480 3.680 76.580 ;
        RECT 2.420 26.580 228.500 68.480 ;
        RECT 2.420 18.480 3.680 26.580 ;
        RECT 2.420 11.100 228.500 18.480 ;
  END
END sub_module16
END LIBRARY

